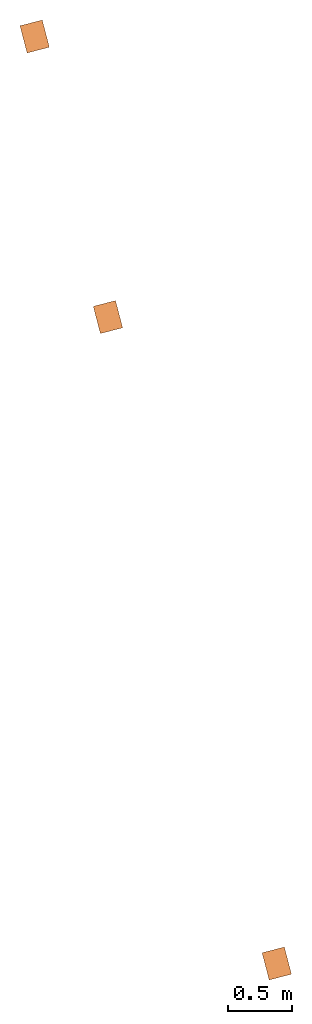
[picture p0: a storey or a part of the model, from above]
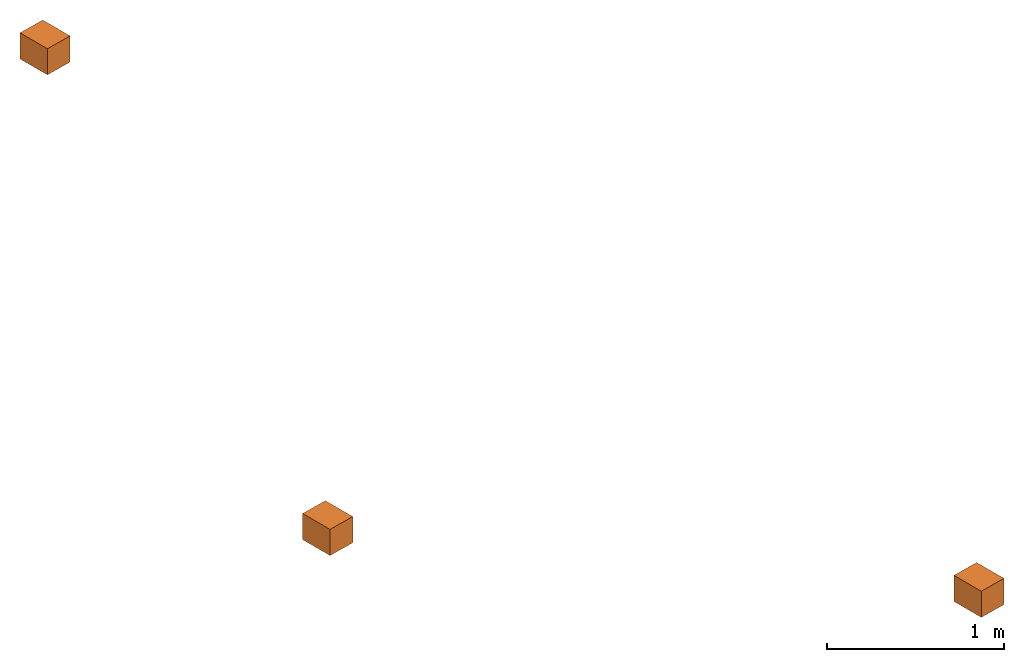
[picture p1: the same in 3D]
Properties of the parts of a building model (IFC2X3), part 1 of 2

# File
Description: ViewDefinition [CoordinationView_V2.0]
Time: 2019-01-15T11:54:13
Written by: The EXPRESS Data Manager Version 5.02.0100.07 : 28 Aug 2013
Made in: 20170223_1515(x64) - Exporter 18.0.0.420 - Alternate UI 18.0.0.420
Comment: STEP Physical File produced by: The EXPRESS Data Manager Version 5.02.0100.07 : 28 Aug 2013 * Module: EDMstepFileFactory/EDMstandAlone * Creation date: Tue Jan 15 11:54:13 2019 * Host: p130-T5-12 * Database: C:\Users\bac\AppData\Local\Temp\{CE2FFFC3-3B57-4D53-86EA-6668387194BC}\ifc * Database version: 5507 * Database creation date: Tue Jan 15 11:53:54 2019 * Schema: IFC2X3 * Model: DataRepository.ifc * Model creation date: Tue Jan 15 11:53:54 2019 * Header model: DataRepository.ifc_HeaderModel * Header model creation date: Tue Jan 15 11:53:54 2019 * EDMuser: sdai-user * EDMgroup: sdai-group * License ID and type: 5605 : Permanent license. Expiry date: * EDMstepFileFactory options: 020000

# IfcProject
LongName: LE HAVRE - LECESNE - 58 HN

# IfcSite, Default
RefLatitude: 49, 29, 35, 967407; RefLongitude: 0, 7, 10, 411264; RefElevation: 400 cm

# IfcBuilding, CAGE 03
LongName: CAGE 03
Pset_BuildingCommon - NumberOfStoreys: 22

# IfcBuildingStorey (22)
In: CAGE 03
Name | LongName | Elevation (cm)
±0.00 | ±0.00 | -400
+3.45 | +3.45 | -55
+3.50 | +3.50 | -50
+3.53 | +3.53 | -47
+3.58 | +3.58 | -42
+3.61 | +3.61 | -39
+3.66 | +3.66 | -34
+3.69 | +3.69 | -31
+3.74 | +3.74 | -26
+3.77 | +3.77 | -23
RDC | RDC | -1.08287e-13
Ac RDC | Ac RDC | 65
R+1 | R+1 | 340
Ac R+1 | Ac R+1 | 385
R+2 | R+2 | 610
Ac R+2 | Ac R+2 | 675
R+3 | R+3 | 880
Ac R+3 | Ac R+3 | 968
R+4 | R+4 | 1150
R+5 | R+5 | 1420
R+6 | R+6 | 1690
Acrotère | Acrotère | 1795

# IfcBeam: 100x20ht (4)
Type - ElementType: 100x20ht; PredefinedType: BEAM; Material: Béton, C25/30
Pset_BeamCommon - LoadBearing: yes; IsExternal: no; Slope: 0 deg; Reference: 100x20ht; Span: 366 cm
Name (BBGO-Poutre rect:100x20ht:...) | In
1579181 | R+5
1588789 | R+4
1595613 | R+3
1606648 | R+2

# IfcBeam: 16x20ht (2)
In: R+2
Type - ElementType: 16x20ht; PredefinedType: BEAM; Material: Béton, C25/30
Pset_BeamCommon - LoadBearing: yes; IsExternal: no; Slope: 0 deg; Reference: 16x20ht
Name (BBGO-Poutre rect:16x20ht:...) | Span (cm)
1604822 | 124
1604825 | 122

# IfcBeam: 18x20ht (14)
Type - ElementType: 18x20ht; PredefinedType: BEAM; Material: Béton, C25/30
Pset_BeamCommon - LoadBearing: yes; IsExternal: no; Slope: 0 deg; Reference: 18x20ht
Name (BBGO-Poutre rect:18x20ht:...) | In | Span (cm)
1467736 | R+5 | 140
1467887 | R+5 | 140
1471738 | R+4 | 122
1594888 | R+3 | 140
1594921 | R+3 | 151.5
1595572 | R+3 | 151.5
1602779 | R+2 | 194
1602781 | R+2 | 200
1604551 | R+2 | 201
1604553 | R+2 | 207
1604658 | R+2 | 194
1604660 | R+2 | 200
1604741 | R+2 | 201
1604743 | R+2 | 207

# IfcBeam: 20x20ht (20)
Type - ElementType: 20x20ht; PredefinedType: BEAM; Material: Béton, C25/30
Pset_BeamCommon - LoadBearing: yes; IsExternal: no; Slope: 0 deg; Reference: 20x20ht
Name (BBGO-Poutre rect:20x20ht:...) | In | Span (cm)
1464487 | R+5 | 155.146
1469260 | R+5 | 160.277
1470163 | R+4 | 155.146
1471747 | R+4 | 160.277
1523368 | R+6 | 164
1580110 | R+5 | 188.891
1588794 | R+4 | 188.891
1594171 | R+3 | 155.146
1595688 | R+3 | 92.2657
1603458 | R+2 | 183.175
1606651 | R+2 | 92.2657
1664121 | R+5 | 154
1664836 | R+4 | 164
1665448 | R+3 | 164
1666531 | R+2 | 164
1666589 | R+2 | 140
1666734 | R+2 | 122
1755034 | +3.66 | 147
1775143 | +3.74 | 147
1775324 | +3.58 | 125

# IfcBeam: 30x20ht (2)
Type - ElementType: 30x20ht; PredefinedType: BEAM; Material: Béton, C25/30
Pset_BeamCommon - LoadBearing: yes; IsExternal: no; Slope: 0 deg; Reference: 30x20ht; Span: 170.852 cm
Name (BBGO-Poutre rect:30x20ht:...) | In
1468716 | R+5
1588786 | R+4

# IfcBeam: 40x20ht, BBGO-Poutre rect:40x20ht:1666184
In: R+2
Type - ElementType: 40x20ht; PredefinedType: BEAM; Material: Béton, C25/30
Pset_BeamCommon - LoadBearing: yes; IsExternal: no; Slope: 0 deg; Reference: 40x20ht; Span: 251 cm

# IfcBeam: 40x23ht, BBGO-Poutre rect:40x23ht:3285993
In: R+1
Type - ElementType: 40x23ht; PredefinedType: BEAM; Material: Béton, C25/30
Pset_BeamCommon - LoadBearing: yes; IsExternal: no; Slope: 0 deg; Reference: 40x23ht; Span: 178 cm

# IfcBeam: 40x80ht, BBGO-Poutre rect:40x80ht:3182657
In: +3.58
Type - ElementType: 40x80ht; PredefinedType: BEAM; Material: Béton, C25/30
Pset_BeamCommon - LoadBearing: yes; IsExternal: no; Slope: 0 deg; Reference: 40x80ht; Span: 398 cm

# IfcBeam: 40x80ht (26)
Type - ElementType: 40x80ht; PredefinedType: BEAM; Material: Béton, C25/30, <Unnamed>
Pset_BeamCommon - LoadBearing: yes; IsExternal: no; Slope: 0 deg; Reference: 40x80ht
Name (BBGO-Poutre rect:40x80ht:...) | In | Span (cm) | Material
1390465 | R+1 | 468
1396344 | R+1 | 576 | Béton, C25/30
1403484 | R+1 | 399 | Béton, C25/30
1404484 | R+1 | 399.771 | Béton, C25/30
1404595 | R+1 | 178.243 | Béton, C25/30
1404652 | R+1 | 534.499 | Béton, C25/30
1683414 | +3.66 | 256.5 | Béton, C25/30
1686917 | +3.74 | 457 | Béton, C25/30
1687021 | +3.74 | 515 | Béton, C25/30
1687140 | +3.58 | 515 | Béton, C25/30
1687440 | +3.58 | 453.5 | Béton, C25/30
1687557 | +3.58 | 741.5 | Béton, C25/30
1687639 | +3.58 | 579 | Béton, C25/30
1687887 | +3.66 | 692.919 | Béton, C25/30
1690029 | +3.66 | 464 | Béton, C25/30
1690128 | +3.66 | 501 | Béton, C25/30
1692204 | +3.66 | 640.137 | Béton, C25/30
1702050 | +3.74 | 510 | Béton, C25/30
1702220 | +3.74 | 511 | Béton, C25/30
1702897 | +3.74 | 656 | Béton, C25/30
1703066 | +3.58 | 515 | Béton, C25/30
1703503 | +3.58 | 706 | Béton, C25/30
1704326 | +3.58 | 260 | Béton, C25/30
1704421 | +3.58 | 480 | Béton, C25/30
1707273 | +3.50 | 537 | Béton, C25/30
1708009 | +3.50 | 284.5 | Béton, C25/30

# IfcBeam: 50x20ht (2)
Type - ElementType: 50x20ht; PredefinedType: BEAM; Material: Béton, C25/30
Pset_BeamCommon - LoadBearing: yes; IsExternal: no; Slope: 0 deg; Reference: 50x20ht; Span: 263 cm
Name (BBGO-Poutre rect:50x20ht:...) | In
1467465 | R+5
1588782 | R+4

# IfcBeam: 50x70ht, BBGO-Poutre rect:50x70ht:1394691
In: R+1
Type - ElementType: 50x70ht; PredefinedType: BEAM; Material: Béton, C25/30
Pset_BeamCommon - LoadBearing: yes; IsExternal: no; Slope: 0 deg; Reference: 50x70ht; Span: 135.263 cm

# IfcBeam: 70x100ht, BBGO-Poutre rect:70x100ht:3188013
In: +3.50
Type - ElementType: 70x100ht; PredefinedType: BEAM; Material: Béton, C25/30
Pset_BeamCommon - LoadBearing: yes; IsExternal: no; Slope: 0 deg; Reference: 70x100ht; Span: 320.487 cm

# IfcBeam: 70x20ht (2)
Type - ElementType: 70x20ht; PredefinedType: BEAM; Material: Béton, C25/30
Pset_BeamCommon - LoadBearing: yes; IsExternal: no; Slope: 0 deg; Reference: 70x20ht; Span: 291.5 cm
Name (BBGO-Poutre rect:70x20ht:...) | In
1467127 | R+5
1588775 | R+4

# IfcBeam: 70x80ht, BBGO-Poutre rect:70x80ht:1686509
In: +3.66
Type - ElementType: 70x80ht; PredefinedType: BEAM; Material: Béton, C25/30
Pset_BeamCommon - LoadBearing: yes; IsExternal: no; Slope: 0 deg; Reference: 70x80ht; Span: 754 cm

# IfcBeam: 80x100ht, BBGO-Poutre rect:80x100ht:1634485
In: R+1
Type - ElementType: 80x100ht; PredefinedType: BEAM; Material: Béton, C25/30
Pset_BeamCommon - LoadBearing: yes; IsExternal: no; Slope: 0 deg; Reference: 80x100ht; Span: 926.545 cm

# IfcBeam: BBGO-Poutre rect:100x100ht, BBGO-Poutre rect:100x100ht:1693027
In: +3.66
Type - PredefinedType: BEAM
Material: Béton, C25/30
Pset_BeamCommon - LoadBearing: yes; IsExternal: no; Slope: 0 deg; Reference: 100x100ht; Span: 349.714 cm

# IfcBeam: BBGO-Poutre rect:16x50ht (2)
In: R+3
Type - PredefinedType: BEAM
Material: Béton, C25/30
Pset_BeamCommon - LoadBearing: yes; IsExternal: no; Slope: 0 deg; Reference: 16x50ht; Span: 124 cm
Name (BBGO-Poutre rect:16x50ht:...)
1594637
1595212

# IfcBeam: BBGO-Poutre rect:18x100ht, BBGO-Poutre rect:18x100ht:1404859
In: R+1
Type - PredefinedType: BEAM
Material: Béton, C25/30
Pset_BeamCommon - LoadBearing: yes; IsExternal: no; Slope: 0 deg; Reference: 18x100ht; Span: 574.707 cm

# IfcBeam: BBGO-Poutre rect:18x113ht (3)
Type - PredefinedType: BEAM
Material: Béton, C25/30
Pset_BeamCommon - LoadBearing: yes; IsExternal: no; Slope: 0 deg; Reference: 18x113ht; Span: 178 cm
Name (BBGO-Poutre rect:18x113ht:...) | In
1701175 | +3.66
1701721 | +3.74
1703309 | +3.58

# IfcBeam: BBGO-Poutre rect:18x115ht (9)
Type - PredefinedType: BEAM
Material: Béton, C25/30
Pset_BeamCommon - LoadBearing: yes; IsExternal: no; Slope: 0 deg; Reference: 18x115ht
Name (BBGO-Poutre rect:18x115ht:...) | In | Span (cm)
1701300 | +3.66 | 187
1701547 | +3.66 | 329
1701560 | +3.66 | 207
1701719 | +3.74 | 187
1701723 | +3.74 | 340
1701725 | +3.74 | 207
1703307 | +3.58 | 187
1703311 | +3.58 | 329
1703313 | +3.58 | 320

# IfcBeam: BBGO-Poutre rect:18x149ht (7)
Type - PredefinedType: BEAM
Material: Béton, C25/30
Pset_BeamCommon - LoadBearing: yes; IsExternal: no; Slope: 0 deg; Reference: 18x149ht
Name (BBGO-Poutre rect:18x149ht:...) | In | Span (cm)
1460876 | Acrotère | 566.165
1462445 | R+5 | 617.413
1462552 | R+5 | 480
1462619 | R+5 | 482
1462693 | R+5 | 480
1471988 | R+5 | 553.046
1472036 | R+5 | 222.13

# IfcBeam: BBGO-Poutre rect:18x35ht (4)
Type - PredefinedType: BEAM
Material: Béton, C25/30
Pset_BeamCommon - LoadBearing: yes; IsExternal: no; Slope: 0 deg; Reference: 18x35ht
Name (BBGO-Poutre rect:18x35ht:...) | In | Span (cm)
1469084 | R+5 | 233
1469165 | R+5 | 378
1471741 | R+4 | 233
1471744 | R+4 | 378

# IfcBeam: BBGO-Poutre rect:18x40ht (6)
Type - PredefinedType: BEAM
Material: Béton, C25/30
Pset_BeamCommon - LoadBearing: yes; IsExternal: no; Slope: 0 deg; Reference: 18x40ht
Name (BBGO-Poutre rect:18x40ht:...) | In | Span (cm)
1460390 | R+6 | 430
1461010 | R+6 | 477.369
1594353 | R+3 | 218
1594355 | R+3 | 224
1595137 | R+3 | 218
1595139 | R+3 | 224

# IfcBeam: BBGO-Poutre rect:18x44ht (4)
In: R+6
Type - PredefinedType: BEAM
Material: Béton, C25/30
Pset_BeamCommon - LoadBearing: yes; IsExternal: no; Slope: 0 deg; Reference: 18x44ht
Name (BBGO-Poutre rect:18x44ht:...) | Span (cm)
1456528 | 221.652
1456573 | 318.081
1460520 | 189
1460558 | 410

# IfcBeam: BBGO-Poutre rect:18x45ht (4)
In: R+1
Type - PredefinedType: BEAM
Material: Béton, C25/30
Pset_BeamCommon - LoadBearing: yes; IsExternal: no; Slope: 0 deg; Reference: 18x45ht
Name (BBGO-Poutre rect:18x45ht:...) | Span (cm)
1393045 | 282
1407809 | 284
1407833 | 282
1428806 | 158.699

# IfcBeam: BBGO-Poutre rect:18x50ht (4)
In: R+3
Type - PredefinedType: BEAM
Material: Béton, C25/30
Pset_BeamCommon - LoadBearing: yes; IsExternal: no; Slope: 0 deg; Reference: 18x50ht
Name (BBGO-Poutre rect:18x50ht:...) | Span (cm)
1594244 | 218
1594278 | 224
1595274 | 218
1595276 | 224

# IfcBeam: BBGO-Poutre rect:18x60ht (6)
Type - PredefinedType: BEAM
Material: Béton, C25/30
Pset_BeamCommon - LoadBearing: yes; IsExternal: no; Slope: 0 deg; Reference: 18x60ht
Name (BBGO-Poutre rect:18x60ht:...) | In | Span (cm)
1698657 | +3.74 | 267.586
1699916 | +3.74 | 514
1700543 | +3.74 | 524
1700562 | +3.74 | 274
1700807 | +3.74 | 514
1704848 | +3.58 | 538

# IfcBeam: BBGO-Poutre rect:18x62ht (5)
In: R+1
Type - PredefinedType: BEAM
Material: Béton, C25/30
Pset_BeamCommon - LoadBearing: yes; IsExternal: no; Reference: 18x62ht; Slope: 0 deg
Name (BBGO-Poutre rect:18x62ht:...) | Span (cm)
1387844 | 489
1388128 | 303
1388225 | 209.113
1408479 | 86.4551
1408550 | 272.054

# IfcBeam: BBGO-Poutre rect:18x70ht, BBGO-Poutre rect:18x70ht:1689230
In: +3.66
Type - PredefinedType: BEAM
Material: Béton, C25/30
Pset_BeamCommon - LoadBearing: yes; IsExternal: no; Slope: 0 deg; Reference: 18x70ht; Span: 459 cm

# IfcBeam: BBGO-Poutre rect:18x75ht, BBGO-Poutre rect:18x75ht:1685928
In: +3.74
Type - PredefinedType: BEAM
Material: Béton, C25/30
Pset_BeamCommon - LoadBearing: yes; IsExternal: no; Slope: 0 deg; Reference: 18x75ht; Span: 484 cm

# IfcBeam: BBGO-Poutre rect:18x80ht (9)
Type - PredefinedType: BEAM
Material: Béton, C25/30
Pset_BeamCommon - LoadBearing: yes; IsExternal: no; Slope: 0 deg; Reference: 18x80ht
Name (BBGO-Poutre rect:18x80ht:...) | In | Span (cm)
1678249 | +3.66 | 586
1684312 | +3.66 | 469
1685654 | +3.74 | 491
1701363 | +3.66 | 156
1701836 | +3.74 | 156
1703319 | +3.58 | 156
1705288 | +3.58 | 252.441
1717493 | +3.58 | 69
1758508 | +3.74 | 15

# IfcBeam: BBGO-Poutre rect:18x89ht (18)
Type - PredefinedType: BEAM
Material: Béton, C25/30
Pset_BeamCommon - LoadBearing: yes; IsExternal: no; Slope: 0 deg; Reference: 18x89ht
Name (BBGO-Poutre rect:18x89ht:...) | In | Span (cm)
1470154 | R+4 | 480
1470156 | R+4 | 482
1470158 | R+4 | 480
1471070 | R+3 | 480
1471072 | R+3 | 482
1471074 | R+3 | 480
1471102 | R+2 | 480
1471104 | R+2 | 482
1471106 | R+2 | 480
1471449 | R+4 | 617.413
1471840 | R+4 | 553.046
1471866 | R+4 | 222.13
1478545 | R+3 | 617.413
1478831 | R+3 | 553.046
1478833 | R+3 | 222.13
1479287 | R+2 | 617.413
1479291 | R+2 | 553.046
1479293 | R+2 | 222.13

# IfcBeam: BBGO-Poutre rect:25x45ht (2)
In: R+1
Type - PredefinedType: BEAM
Material: Béton, C25/30
Pset_BeamCommon - LoadBearing: yes; IsExternal: no; Slope: 0 deg; Reference: 25x45ht
Name (BBGO-Poutre rect:25x45ht:...) | Span (cm)
1394172 | 183
1406665 | 176

# IfcBeam: BBGO-Poutre rect:25x60ht (2)
In: +3.74
Type - PredefinedType: BEAM
Material: Béton, C25/30
Pset_BeamCommon - LoadBearing: yes; IsExternal: no; Slope: 0 deg; Reference: 25x60ht
Name (BBGO-Poutre rect:25x60ht:...) | Span (cm)
1691024 | 495
1691301 | 647

# IfcBeam: BBGO-Poutre rect:25x75ht, BBGO-Poutre rect:25x75ht:1702517
In: +3.74
Type - PredefinedType: BEAM
Material: Béton, C25/30
Pset_BeamCommon - LoadBearing: yes; IsExternal: no; Slope: 0 deg; Reference: 25x75ht; Span: 493 cm

# IfcBeam: BBGO-Poutre rect:25x80ht (5)
Type - PredefinedType: BEAM
Material: Béton, C25/30
Pset_BeamCommon - LoadBearing: yes; IsExternal: no; Slope: 0 deg; Reference: 25x80ht
Name (BBGO-Poutre rect:25x80ht:...) | In | Span (cm)
1699639 | +3.66 | 695
1702635 | +3.74 | 334
1707469 | +3.50 | 314.814
1707831 | +3.50 | 528.138
1708224 | +3.50 | 291.294

# IfcBeam: BBGO-Poutre rect:30x45ht (2)
In: R+1
Type - PredefinedType: BEAM
Material: Béton, C25/30
Pset_BeamCommon - LoadBearing: yes; IsExternal: no; Slope: 0 deg; Reference: 30x45ht
Name (BBGO-Poutre rect:30x45ht:...) | Span (cm)
1401985 | 260.5
1402226 | 237

# IfcBeam: BBGO-Poutre rect:30x50ht, BBGO-Poutre rect:30x50ht:2342210
In: R+1
Type - PredefinedType: BEAM
Material: Béton, C25/30
Pset_BeamCommon - LoadBearing: yes; IsExternal: no; Slope: 0 deg; Reference: 30x50ht; Span: 419.826 cm

# IfcBeam: BBGO-Poutre rect:30x60ht (4)
In: +3.50
Type - PredefinedType: BEAM
Material: Béton, C25/30
Pset_BeamCommon - LoadBearing: yes; IsExternal: no; Slope: 0 deg; Reference: 30x60ht; Span: 350 cm
Name (BBGO-Poutre rect:30x60ht:...)
3117109
3117535
3117598
3117718

# IfcBeam: BBGO-Poutre rect:30x80ht (10)
Type - PredefinedType: BEAM
Material: Béton, C25/30
Pset_BeamCommon - LoadBearing: yes; IsExternal: no; Slope: 0 deg; Reference: 30x80ht
Name (BBGO-Poutre rect:30x80ht:...) | In | Span (cm)
1689533 | +3.66 | 510
1691867 | +3.77 | 371.045
1692765 | +3.66 | 624.328
1693319 | +3.66 | 186.5
1699210 | +3.74 | 343
1707919 | +3.50 | 348.438
2337563 | +3.74 | 225
2337755 | +3.74 | 225
2340572 | +3.74 | 143
2340669 | +3.74 | 143

# IfcBeam: BBGO-Poutre rect:30x86ht, BBGO-Poutre rect:30x86ht:1692640
In: +3.77
Type - PredefinedType: BEAM
Material: Béton, C25/30
Pset_BeamCommon - LoadBearing: yes; IsExternal: no; Slope: 0 deg; Reference: 30x86ht; Span: 289 cm

# IfcBeam: BBGO-Poutre rect:35x100ht (4)
In: R+1
Type - PredefinedType: BEAM
Material: Béton, C25/30
Pset_BeamCommon - LoadBearing: yes; IsExternal: no; Slope: 0 deg; Reference: 35x100ht
Name (BBGO-Poutre rect:35x100ht:...) | Span (cm)
1401092 | 227
1401320 | 233
1401492 | 227
1401494 | 233

# IfcBeam: BBGO-Poutre rect:35x44ht, BBGO-Poutre rect:35x44ht:1456888
In: R+6
Type - PredefinedType: BEAM
Material: Béton, C25/30
Pset_BeamCommon - LoadBearing: yes; IsExternal: no; Slope: 0 deg; Reference: 35x44ht; Span: 798 cm

# IfcBeam: BBGO-Poutre rect:35x75ht (2)
In: R+1
Type - PredefinedType: BEAM
Material: Béton, C25/30
Pset_BeamCommon - LoadBearing: yes; IsExternal: no; Slope: 0 deg; Reference: 35x75ht; Span: 156 cm
Name (BBGO-Poutre rect:35x75ht:...)
1645117
1645243

# IfcBeam: BBGO-Poutre rect:35x80ht (2)
In: +3.58
Type - PredefinedType: BEAM
Material: Béton, C25/30
Pset_BeamCommon - LoadBearing: yes; IsExternal: no; Slope: 0 deg; Reference: 35x80ht
Name (BBGO-Poutre rect:35x80ht:...) | Span (cm)
1703919 | 660
1704288 | 252

# IfcBeam: BBGO-Poutre rect:36x101ht (2)
In: +3.66
Type - PredefinedType: BEAM
Material: Béton, C25/30
Pset_BeamCommon - LoadBearing: yes; IsExternal: no; Slope: 0 deg; Reference: 36x101ht
Name (BBGO-Poutre rect:36x101ht:...) | Span (cm)
1706288 | 539.344
1706487 | 410.66

# IfcBeam: BBGO-Poutre rect:40x100ht (15)
In: R+1
Type - PredefinedType: BEAM
Material: Béton, C25/30
Pset_BeamCommon - LoadBearing: yes; IsExternal: no; Slope: 0 deg; Reference: 40x100ht
Name (BBGO-Poutre rect:40x100ht:...) | Span (cm)
1392234 | 480.5
1392454 | 397.391
1392599 | 516.5
1393220 | 752.5
1394944 | 437.5
1395088 | 455
1395167 | 237
1395228 | 237
1395267 | 227
1395270 | 227
1396259 | 152
1400642 | 281.5
1400772 | 330.5
1400857 | 433.499
1402557 | 106.501

# IfcBeam: BBGO-Poutre rect:40x16ht (2)
In: R+3
Type - PredefinedType: BEAM
Material: Béton, C25/30
Pset_BeamCommon - LoadBearing: yes; IsExternal: no; Slope: 0 deg; Reference: 40x16ht
Name (BBGO-Poutre rect:40x16ht:...) | Span (cm)
2397350 | 34
2398709 | 39

# IfcBeam: BBGO-Poutre rect:40x60ht (4)
Type - PredefinedType: BEAM
Material: Béton, C25/30
Pset_BeamCommon - LoadBearing: yes; IsExternal: no; Slope: 0 deg; Reference: 40x60ht
Name (BBGO-Poutre rect:40x60ht:...) | In | Span (cm)
1392805 | R+1 | 360.5
1401913 | R+1 | 389
1698551 | +3.74 | 569
3285272 | R+1 | 199.436

# IfcBeam: BBGO-Poutre rect:40x70ht (3)
In: R+1
Type - PredefinedType: BEAM
Material: Béton, C25/30
Pset_BeamCommon - LoadBearing: yes; IsExternal: no; Slope: 0 deg; Reference: 40x70ht
Name (BBGO-Poutre rect:40x70ht:...) | Span (cm)
1396079 | 368
1401577 | 389
1406589 | 256.5

# IfcBeam: BBGO-Poutre rect:40x75ht (3)
In: R+1
Type - PredefinedType: BEAM
Material: Béton, C25/30
Pset_BeamCommon - LoadBearing: yes; IsExternal: no; Slope: 0 deg; Reference: 40x75ht
Name (BBGO-Poutre rect:40x75ht:...) | Span (cm)
1633729 | 197
1644679 | 188.5
1644749 | 188.5

# IfcBeam: BBGO-Poutre rect:40x90ht (7)
In: R+1
Type - PredefinedType: BEAM
Material: Béton, C25/30
Pset_BeamCommon - LoadBearing: yes; IsExternal: no; Slope: 0 deg; Reference: 40x90ht
Name (BBGO-Poutre rect:40x90ht:...) | Span (cm)
1397843 | 544
1398095 | 274
1400056 | 544
1400127 | 274
1403041 | 695
1403301 | 580
1403924 | 569

# IfcBeam: BBGO-Poutre rect:40x91ht (2)
In: +3.77
Type - PredefinedType: BEAM
Material: Béton, C25/30
Pset_BeamCommon - LoadBearing: yes; IsExternal: no; Slope: 0 deg; Reference: 40x91ht
Name (BBGO-Poutre rect:40x91ht:...) | Span (cm)
1691365 | 106
1692473 | 244.674

# IfcBeam: BBGO-Poutre rect:45x101ht (2)
In: +3.66
Type - PredefinedType: BEAM
Material: Béton, C25/30
Pset_BeamCommon - LoadBearing: yes; IsExternal: no; Slope: 0 deg; Reference: 45x101ht
Name (BBGO-Poutre rect:45x101ht:...) | Span (cm)
1705961 | 470.752
1706576 | 483.612

# IfcBeam: BBGO-Poutre rect:45x80ht, BBGO-Poutre rect:45x80ht:1704699
In: +3.58
Type - PredefinedType: BEAM
Material: Béton, C25/30
Pset_BeamCommon - LoadBearing: yes; IsExternal: no; Slope: 0 deg; Reference: 45x80ht; Span: 256.5 cm

# IfcBeam: BBGO-Poutre rect:50x100ht (7)
In: R+1
Type - PredefinedType: BEAM
Material: Béton, C25/30
Pset_BeamCommon - LoadBearing: yes; IsExternal: no; Slope: 0 deg; Reference: 50x100ht
Name (BBGO-Poutre rect:50x100ht:...) | Span (cm)
1393466 | 695
1398620 | 489
1398963 | 590
1399015 | 501
1402654 | 747
1402804 | 540
1402851 | 609

# IfcBeam: BBGO-Poutre rect:50x110ht, BBGO-Poutre rect:50x110ht:1700393
In: +3.74
Type - PredefinedType: BEAM
Material: Béton, C25/30
Pset_BeamCommon - LoadBearing: yes; IsExternal: no; Slope: 0 deg; Reference: 50x110ht; Span: 532 cm

# IfcBeam: BBGO-Poutre rect:50x70ht (2)
In: R+1
Type - PredefinedType: BEAM
Material: Béton, C25/30
Pset_BeamCommon - LoadBearing: yes; IsExternal: no; Slope: 0 deg; Reference: 50x70ht
Name (BBGO-Poutre rect:50x70ht:...) | Span (cm)
1394042 | 575
1407037 | 403

# IfcBeam: BBGO-Poutre rect:50x80ht (3)
Type - PredefinedType: BEAM
Material: Béton, C25/30
Pset_BeamCommon - LoadBearing: yes; IsExternal: no; Slope: 0 deg; Reference: 50x80ht
Name (BBGO-Poutre rect:50x80ht:...) | In | Span (cm)
1390898 | R+1 | 459
1407191 | R+1 | 528
1707155 | +3.50 | 488.376

# IfcBeam: BBGO-Poutre rect:50x90ht, BBGO-Poutre rect:50x90ht:1390707
In: R+1
Type - PredefinedType: BEAM
Material: Béton, C25/30
Pset_BeamCommon - LoadBearing: yes; IsExternal: no; Slope: 0 deg; Reference: 50x90ht; Span: 468 cm

# IfcBeam: BBGO-Poutre rect:51x45ht, BBGO-Poutre rect:51x45ht:1428907
In: R+1
Type - PredefinedType: BEAM
Material: Béton, C25/30
Pset_BeamCommon - LoadBearing: yes; IsExternal: no; Slope: 0 deg; Reference: 51x45ht; Span: 296.018 cm

# IfcBeam: BBGO-Poutre rect:55x107ht (2)
In: +3.66
Type - PredefinedType: BEAM
Material: Béton, C25/30
Pset_BeamCommon - LoadBearing: yes; IsExternal: no; Slope: 0 deg; Reference: 55x107ht
Name (BBGO-Poutre rect:55x107ht:...) | Span (cm)
1688491 | 164.022
1689137 | 498

# IfcBeam: BBGO-Poutre rect:55x80ht, BBGO-Poutre rect:55x80ht:1688154
In: +3.66
Type - PredefinedType: BEAM
Material: Béton, C25/30
Pset_BeamCommon - LoadBearing: yes; IsExternal: no; Slope: 0 deg; Reference: 55x80ht; Span: 450 cm

# IfcBeam: BBGO-Poutre rect:60x100ht (3)
In: R+1
Type - PredefinedType: BEAM
Material: Béton, C25/30
Pset_BeamCommon - LoadBearing: yes; IsExternal: no; Slope: 0 deg; Reference: 60x100ht
Name (BBGO-Poutre rect:60x100ht:...) | Span (cm)
1397119 | 862
1398215 | 791
1400321 | 867

# IfcBeam: BBGO-Poutre rect:60x80ht (6)
Type - PredefinedType: BEAM
Material: Béton, C25/30
Pset_BeamCommon - LoadBearing: yes; IsExternal: no; Slope: 0 deg; Reference: 60x80ht
Name (BBGO-Poutre rect:60x80ht:...) | In | Span (cm)
1687762 | +3.66 | 135.453
1688713 | +3.66 | 596.5
1697774 | +3.74 | 102.188
1698284 | +3.74 | 568.85
1700316 | +3.74 | 519
2341871 | +3.66 | 322

# IfcBeam: BBGO-Poutre rect:60x90ht (3)
In: R+1
Type - PredefinedType: BEAM
Material: Béton, C25/30
Pset_BeamCommon - LoadBearing: yes; IsExternal: no; Slope: 0 deg; Reference: 60x90ht
Name (BBGO-Poutre rect:60x90ht:...) | Span (cm)
1391032 | 559
1391274 | 575
1392754 | 566.5

# IfcBeam: BBGO-Poutre rect:65x100ht, BBGO-Poutre rect:65x100ht:1692812
In: +3.66
Type - PredefinedType: BEAM
Material: Béton, C25/30
Pset_BeamCommon - LoadBearing: yes; IsExternal: no; Slope: 0 deg; Reference: 65x100ht; Span: 847.105 cm

# IfcBeam: BBGO-Poutre rect:65x45ht (3)
In: R+1
Type - PredefinedType: BEAM
Material: Béton, C25/30
Pset_BeamCommon - LoadBearing: yes; IsExternal: no; Slope: 0 deg; Reference: 65x45ht
Name (BBGO-Poutre rect:65x45ht:...) | Span (cm)
1396215 | 495
1396510 | 495
1401807 | 497.5

# IfcBeam: BBGO-Poutre rect:70x80ht (3)
In: +3.74
Type - PredefinedType: BEAM
Material: Béton, C25/30
Pset_BeamCommon - LoadBearing: yes; IsExternal: no; Slope: 0 deg; Reference: 70x80ht
Name (BBGO-Poutre rect:70x80ht:...) | Span (cm)
1684769 | 487
1685497 | 804
1716617 | 661

# IfcBeam: BBGO-Poutre rect:70x90ht (2)
In: R+1
Type - PredefinedType: BEAM
Material: Béton, C25/30
Pset_BeamCommon - LoadBearing: yes; IsExternal: no; Slope: 0 deg; Reference: 70x90ht
Name (BBGO-Poutre rect:70x90ht:...) | Span (cm)
1398422 | 575
1399689 | 580

# IfcBeam: BBGO-Poutre rect:80x100ht (5)
Type - PredefinedType: BEAM
Material: Béton, C25/30
Pset_BeamCommon - LoadBearing: yes; IsExternal: no; Slope: 0 deg; Reference: 80x100ht
Name (BBGO-Poutre rect:80x100ht:...) | In | Span (cm)
1402473 | R+1 | 867
1705394 | +3.50 | 91.0043
1705895 | +3.50 | 521.4
3184185 | +3.58 | 170
3186767 | +3.58 | 510.114

# IfcBeam: BBGO-Poutre rect:80x45ht, BBGO-Poutre rect:80x45ht:1388635
In: R+1
Type - PredefinedType: BEAM
Material: Béton, C25/30
Pset_BeamCommon - LoadBearing: yes; IsExternal: no; Slope: 0 deg; Reference: 80x45ht; Span: 256.5 cm

# IfcBeam: BBGO-Poutre rect:80x80ht (4)
Type - PredefinedType: BEAM
Material: Béton, C25/30
Pset_BeamCommon - LoadBearing: yes; IsExternal: no; Slope: 0 deg; Reference: 80x80ht
Name (BBGO-Poutre rect:80x80ht:...) | In | Span (cm)
1690715 | +3.66 | 255
1703595 | +3.58 | 498
2341290 | +3.66 | 152
2405490 | +3.77 | 407.373

# IfcBeam: BBGO-Poutre rect:90x70ht (2)
In: +3.74
Type - PredefinedType: BEAM
Material: Béton, C25/30
Pset_BeamCommon - LoadBearing: yes; IsExternal: no; Slope: 0 deg; Reference: 90x70ht
Name (BBGO-Poutre rect:90x70ht:...) | Span (cm)
1693658 | 902.783
1693866 | 42.2729

# IfcBeam: BBGO-Poutre rect:90x90ht, BBGO-Poutre rect:90x90ht:1399750
In: R+1
Type - PredefinedType: BEAM
Material: Béton, C25/30
Pset_BeamCommon - LoadBearing: yes; IsExternal: no; Slope: 0 deg; Reference: 90x90ht; Span: 850 cm

# IfcBeam: Cornière à ailes inégales:L80x60x7 (4)
In: +3.66
Type - PredefinedType: BEAM
Material: Acier structurel - S235
Pset_BeamCommon - LoadBearing: yes; IsExternal: no; Slope: 0 deg; Reference: L80x60x7
Name (Cornière à ailes inégales:L80x60x7:...) | Span (cm)
1879896 | 97.5
1881167 | 97.5
1881275 | 140
1881454 | 140

# IfcBeam: Cornière à ailes égales:L30x4 (3)
In: +3.66
Type - PredefinedType: BEAM
Material: Acier structurel - S235
Pset_BeamCommon - LoadBearing: yes; IsExternal: no; Slope: 0 deg; Reference: L30x4
Name (Cornière à ailes égales:L30x4:...) | Span (cm)
1878539 | 106
1878629 | 24.5
1879489 | 24.5

# IfcBuildingElementProxy: CFO100 P80 (45)
Type - Material: Circuit ECS Retour
Pset_BuildingElementProxyCommon - Reference: CFO100 P80
Name | In
Galette - Résa - PVC1:CFO100 P80:3861348 | R+2
Galette - Résa - PVC1:CFO100 P80:3861380 | R+2
Galette - Résa - PVC1:CFO100 P80:3861387 | R+2
Galette - Résa - PVC1:CFO100 P80:3861394 | R+2
Galette - Résa - PVC1:CFO100 P80:3861396 | R+2
Galette - Résa - PVC1:CFO100 P80:3861402 | R+2
Galette - Résa - PVC1:CFO100 P80:3861410 | R+2
Galette - Résa - PVC1:CFO100 P80:3861412 | R+2
Galette - Résa - PVC1:CFO100 P80:3861423 | R+2
Galette - Résa - PVC1:CFO100 P80:3861425 | R+2
Galette - Résa - PVC1:CFO100 P80:3861432 | R+2
Galette - Résa - PVC1:CFO100 P80:3861436 | R+2
Galette - Résa - PVC2:CFO100 P80:3880356 | R+3
Galette - Résa - PVC2:CFO100 P80:3880362 | R+3
Galette - Résa - PVC2:CFO100 P80:3880373 | R+3
Galette - Résa - PVC2:CFO100 P80:3880377 | R+3
Galette - Résa - PVC2:CFO100 P80:3880392 | R+3
Galette - Résa - PVC2:CFO100 P80:3880402 | R+3
Galette - Résa - PVC2:CFO100 P80:3880404 | R+3
Galette - Résa - PVC2:CFO100 P80:3880414 | R+3
Galette - Résa - PVC2:CFO100 P80:3880428 | R+3
Galette - Résa - PVC2:CFO100 P80:3880435 | R+3
Galette - Résa - PVC2:CFO100 P80:3880441 | R+3
Galette - Résa - PVC2:CFO100 P80:3880449 | R+3
Galette - Résa - PVC3:CFO100 P80:3882960 | R+4
Galette - Résa - PVC3:CFO100 P80:3882966 | R+4
Galette - Résa - PVC3:CFO100 P80:3882979 | R+4
Galette - Résa - PVC3:CFO100 P80:3882987 | R+4
Galette - Résa - PVC3:CFO100 P80:3882996 | R+4
Galette - Résa - PVC3:CFO100 P80:3882998 | R+4
Galette - Résa - PVC3:CFO100 P80:3883009 | R+4
Galette - Résa - PVC3:CFO100 P80:3883022 | R+4
Galette - Résa - PVC3:CFO100 P80:3883029 | R+4
Galette - Résa - PVC3:CFO100 P80:3883035 | R+4
Galette - Résa - PVC3:CFO100 P80:3883043 | R+4
Galette - Résa - PVC4:CFO100 P80:3885499 | R+5
Galette - Résa - PVC4:CFO100 P80:3885505 | R+5
Galette - Résa - PVC4:CFO100 P80:3885516 | R+5
Galette - Résa - PVC4:CFO100 P80:3885519 | R+5
Galette - Résa - PVC4:CFO100 P80:3885528 | R+5
Galette - Résa - PVC4:CFO100 P80:3885530 | R+5
Galette - Résa - PVC4:CFO100 P80:3885541 | R+5
Galette - Résa - PVC4:CFO100 P80:3885552 | R+5
Galette - Résa - PVC4:CFO100 P80:3885559 | R+5
Galette - Résa - PVC4:CFO100 P80:3885567 | R+5

# IfcBuildingElementProxy: CFO100 P90 (45)
Type - Material: Circuit ECS Aller
Pset_BuildingElementProxyCommon - Reference: CFO100 P90
Name | In
Galette - Résa - PVC1:CFO100 P90:3861347 | R+2
Galette - Résa - PVC1:CFO100 P90:3861379 | R+2
Galette - Résa - PVC1:CFO100 P90:3861386 | R+2
Galette - Résa - PVC1:CFO100 P90:3861393 | R+2
Galette - Résa - PVC1:CFO100 P90:3861395 | R+2
Galette - Résa - PVC1:CFO100 P90:3861401 | R+2
Galette - Résa - PVC1:CFO100 P90:3861409 | R+2
Galette - Résa - PVC1:CFO100 P90:3861411 | R+2
Galette - Résa - PVC1:CFO100 P90:3861422 | R+2
Galette - Résa - PVC1:CFO100 P90:3861424 | R+2
Galette - Résa - PVC1:CFO100 P90:3861433 | R+2
Galette - Résa - PVC1:CFO100 P90:3861435 | R+2
Galette - Résa - PVC2:CFO100 P90:3880357 | R+3
Galette - Résa - PVC2:CFO100 P90:3880361 | R+3
Galette - Résa - PVC2:CFO100 P90:3880372 | R+3
Galette - Résa - PVC2:CFO100 P90:3880376 | R+3
Galette - Résa - PVC2:CFO100 P90:3880391 | R+3
Galette - Résa - PVC2:CFO100 P90:3880401 | R+3
Galette - Résa - PVC2:CFO100 P90:3880403 | R+3
Galette - Résa - PVC2:CFO100 P90:3880413 | R+3
Galette - Résa - PVC2:CFO100 P90:3880427 | R+3
Galette - Résa - PVC2:CFO100 P90:3880436 | R+3
Galette - Résa - PVC2:CFO100 P90:3880440 | R+3
Galette - Résa - PVC2:CFO100 P90:3880448 | R+3
Galette - Résa - PVC3:CFO100 P90:3882961 | R+4
Galette - Résa - PVC3:CFO100 P90:3882965 | R+4
Galette - Résa - PVC3:CFO100 P90:3882978 | R+4
Galette - Résa - PVC3:CFO100 P90:3882986 | R+4
Galette - Résa - PVC3:CFO100 P90:3882995 | R+4
Galette - Résa - PVC3:CFO100 P90:3882997 | R+4
Galette - Résa - PVC3:CFO100 P90:3883008 | R+4
Galette - Résa - PVC3:CFO100 P90:3883021 | R+4
Galette - Résa - PVC3:CFO100 P90:3883030 | R+4
Galette - Résa - PVC3:CFO100 P90:3883036 | R+4
Galette - Résa - PVC3:CFO100 P90:3883042 | R+4
Galette - Résa - PVC4:CFO100 P90:3885500 | R+5
Galette - Résa - PVC4:CFO100 P90:3885504 | R+5
Galette - Résa - PVC4:CFO100 P90:3885515 | R+5
Galette - Résa - PVC4:CFO100 P90:3885518 | R+5
Galette - Résa - PVC4:CFO100 P90:3885527 | R+5
Galette - Résa - PVC4:CFO100 P90:3885529 | R+5
Galette - Résa - PVC4:CFO100 P90:3885540 | R+5
Galette - Résa - PVC4:CFO100 P90:3885551 | R+5
Galette - Résa - PVC4:CFO100 P90:3885560 | R+5
Galette - Résa - PVC4:CFO100 P90:3885566 | R+5

# IfcBuildingElementProxy: CFO125 P100, Galette - Résa - PVC:CFO125 P100:3841190
In: R+1
Type - Material: Circuit CHF Retour
Pset_BuildingElementProxyCommon - Reference: CFO125 P100

# IfcBuildingElementProxy: CFO125 P110 (149)
Type - Material: Conduit EU
Pset_BuildingElementProxyCommon - Reference: CFO125 P110
Name | In
Galette - Résa - PVC1:CFO125 P110:3861322 | R+2
Galette - Résa - PVC1:CFO125 P110:3861345 | R+2
Galette - Résa - PVC1:CFO125 P110:3861349 | R+2
Galette - Résa - PVC1:CFO125 P110:3861352 | R+2
Galette - Résa - PVC1:CFO125 P110:3861353 | R+2
Galette - Résa - PVC1:CFO125 P110:3861354 | R+2
Galette - Résa - PVC1:CFO125 P110:3861355 | R+2
Galette - Résa - PVC1:CFO125 P110:3861356 | R+2
Galette - Résa - PVC1:CFO125 P110:3861357 | R+2
Galette - Résa - PVC1:CFO125 P110:3861358 | R+2
Galette - Résa - PVC1:CFO125 P110:3861359 | R+2
Galette - Résa - PVC1:CFO125 P110:3861360 | R+2
Galette - Résa - PVC1:CFO125 P110:3861361 | R+2
Galette - Résa - PVC1:CFO125 P110:3861362 | R+2
Galette - Résa - PVC1:CFO125 P110:3861363 | R+2
Galette - Résa - PVC1:CFO125 P110:3861364 | R+2
Galette - Résa - PVC1:CFO125 P110:3861365 | R+2
Galette - Résa - PVC1:CFO125 P110:3861366 | R+2
Galette - Résa - PVC1:CFO125 P110:3861367 | R+2
Galette - Résa - PVC1:CFO125 P110:3861368 | R+2
Galette - Résa - PVC1:CFO125 P110:3861369 | R+2
Galette - Résa - PVC1:CFO125 P110:3861370 | R+2
Galette - Résa - PVC1:CFO125 P110:3861371 | R+2
Galette - Résa - PVC1:CFO125 P110:3861372 | R+2
Galette - Résa - PVC1:CFO125 P110:3861373 | R+2
Galette - Résa - PVC1:CFO125 P110:3861374 | R+2
Galette - Résa - PVC1:CFO125 P110:3861375 | R+2
Galette - Résa - PVC1:CFO125 P110:3861381 | R+2
Galette - Résa - PVC1:CFO125 P110:3861383 | R+2
Galette - Résa - PVC1:CFO125 P110:3861406 | R+2
Galette - Résa - PVC1:CFO125 P110:3861421 | R+2
Galette - Résa - PVC1:CFO125 P110:3861426 | R+2
Galette - Résa - PVC1:CFO125 P110:3861427 | R+2
Galette - Résa - PVC1:CFO125 P110:3861431 | R+2
Galette - Résa - PVC1:CFO125 P110:3861434 | R+2
Galette - Résa - PVC2:CFO125 P110:3880354 | R+3
Galette - Résa - PVC2:CFO125 P110:3880358 | R+3
Galette - Résa - PVC2:CFO125 P110:3880360 | R+3
Galette - Résa - PVC2:CFO125 P110:3880363 | R+3
Galette - Résa - PVC2:CFO125 P110:3880367 | R+3
Galette - Résa - PVC2:CFO125 P110:3880368 | R+3
Galette - Résa - PVC2:CFO125 P110:3880369 | R+3
Galette - Résa - PVC2:CFO125 P110:3880370 | R+3
Galette - Résa - PVC2:CFO125 P110:3880374 | R+3
Galette - Résa - PVC2:CFO125 P110:3880379 | R+3
Galette - Résa - PVC2:CFO125 P110:3880385 | R+3
Galette - Résa - PVC2:CFO125 P110:3880387 | R+3
Galette - Résa - PVC2:CFO125 P110:3880393 | R+3
Galette - Résa - PVC2:CFO125 P110:3880394 | R+3
Galette - Résa - PVC2:CFO125 P110:3880396 | R+3
Galette - Résa - PVC2:CFO125 P110:3880399 | R+3
Galette - Résa - PVC2:CFO125 P110:3880400 | R+3
Galette - Résa - PVC2:CFO125 P110:3880408 | R+3
Galette - Résa - PVC2:CFO125 P110:3880409 | R+3
Galette - Résa - PVC2:CFO125 P110:3880411 | R+3
Galette - Résa - PVC2:CFO125 P110:3880416 | R+3
Galette - Résa - PVC2:CFO125 P110:3880425 | R+3
Galette - Résa - PVC2:CFO125 P110:3880429 | R+3
Galette - Résa - PVC2:CFO125 P110:3880431 | R+3
Galette - Résa - PVC2:CFO125 P110:3880434 | R+3
Galette - Résa - PVC2:CFO125 P110:3880437 | R+3
Galette - Résa - PVC2:CFO125 P110:3880439 | R+3
Galette - Résa - PVC2:CFO125 P110:3880442 | R+3
Galette - Résa - PVC2:CFO125 P110:3880444 | R+3
Galette - Résa - PVC2:CFO125 P110:3880445 | R+3
Galette - Résa - PVC2:CFO125 P110:3880447 | R+3
Galette - Résa - PVC2:CFO125 P110:3880450 | R+3
Galette - Résa - PVC3:CFO125 P110:3882958 | R+4
Galette - Résa - PVC3:CFO125 P110:3882962 | R+4
Galette - Résa - PVC3:CFO125 P110:3882964 | R+4
Galette - Résa - PVC3:CFO125 P110:3882968 | R+4
Galette - Résa - PVC3:CFO125 P110:3882972 | R+4
Galette - Résa - PVC3:CFO125 P110:3882973 | R+4
Galette - Résa - PVC3:CFO125 P110:3882974 | R+4
Galette - Résa - PVC3:CFO125 P110:3882976 | R+4
Galette - Résa - PVC3:CFO125 P110:3882980 | R+4
Galette - Résa - PVC3:CFO125 P110:3882982 | R+4
Galette - Résa - PVC3:CFO125 P110:3882983 | R+4
Galette - Résa - PVC3:CFO125 P110:3882988 | R+4
Galette - Résa - PVC3:CFO125 P110:3882989 | R+4
Galette - Résa - PVC3:CFO125 P110:3882991 | R+4
Galette - Résa - PVC3:CFO125 P110:3882993 | R+4
Galette - Résa - PVC3:CFO125 P110:3882994 | R+4
Galette - Résa - PVC3:CFO125 P110:3883002 | R+4
Galette - Résa - PVC3:CFO125 P110:3883005 | R+4
Galette - Résa - PVC3:CFO125 P110:3883006 | R+4
Galette - Résa - PVC3:CFO125 P110:3883011 | R+4
Galette - Résa - PVC3:CFO125 P110:3883019 | R+4
Galette - Résa - PVC3:CFO125 P110:3883023 | R+4
Galette - Résa - PVC3:CFO125 P110:3883025 | R+4
Galette - Résa - PVC3:CFO125 P110:3883028 | R+4
Galette - Résa - PVC3:CFO125 P110:3883031 | R+4
Galette - Résa - PVC3:CFO125 P110:3883034 | R+4
Galette - Résa - PVC3:CFO125 P110:3883037 | R+4
Galette - Résa - PVC3:CFO125 P110:3883038 | R+4
Galette - Résa - PVC3:CFO125 P110:3883039 | R+4
Galette - Résa - PVC3:CFO125 P110:3883041 | R+4
Galette - Résa - PVC3:CFO125 P110:3883044 | R+4
Galette - Résa - PVC3:CFO125 P110:3883046 | R+4
Galette - Résa - PVC4:CFO125 P110:3885491 | R+5
Galette - Résa - PVC4:CFO125 P110:3885495 | R+5
Galette - Résa - PVC4:CFO125 P110:3885497 | R+5
Galette - Résa - PVC4:CFO125 P110:3885501 | R+5
Galette - Résa - PVC4:CFO125 P110:3885503 | R+5
Galette - Résa - PVC4:CFO125 P110:3885509 | R+5
Galette - Résa - PVC4:CFO125 P110:3885510 | R+5
Galette - Résa - PVC4:CFO125 P110:3885511 | R+5
Galette - Résa - PVC4:CFO125 P110:3885513 | R+5
Galette - Résa - PVC4:CFO125 P110:3885520 | R+5
Galette - Résa - PVC4:CFO125 P110:3885521 | R+5
Galette - Résa - PVC4:CFO125 P110:3885523 | R+5
Galette - Résa - PVC4:CFO125 P110:3885525 | R+5
Galette - Résa - PVC4:CFO125 P110:3885526 | R+5
Galette - Résa - PVC4:CFO125 P110:3885534 | R+5
Galette - Résa - PVC4:CFO125 P110:3885537 | R+5
Galette - Résa - PVC4:CFO125 P110:3885538 | R+5
Galette - Résa - PVC4:CFO125 P110:3885542 | R+5
Galette - Résa - PVC4:CFO125 P110:3885553 | R+5
Galette - Résa - PVC4:CFO125 P110:3885556 | R+5
Galette - Résa - PVC4:CFO125 P110:3885557 | R+5
Galette - Résa - PVC4:CFO125 P110:3885561 | R+5
Galette - Résa - PVC4:CFO125 P110:3885563 | R+5
Galette - Résa - PVC4:CFO125 P110:3885565 | R+5
Galette - Résa - PVC4:CFO125 P110:3885568 | R+5
Galette - Résa - PVC5:CFO125 P110:3888138 | R+6
Galette - Résa - PVC5:CFO125 P110:3888140 | R+6
Galette - Résa - PVC5:CFO125 P110:3888142 | R+6
Galette - Résa - PVC5:CFO125 P110:3888144 | R+6
Galette - Résa - PVC5:CFO125 P110:3888148 | R+6
Galette - Résa - PVC5:CFO125 P110:3888149 | R+6
Galette - Résa - PVC5:CFO125 P110:3888150 | R+6
Galette - Résa - PVC5:CFO125 P110:3888152 | R+6
Galette - Résa - PVC5:CFO125 P110:3888157 | R+6
Galette - Résa - PVC5:CFO125 P110:3888158 | R+6
Galette - Résa - PVC5:CFO125 P110:3888160 | R+6
Galette - Résa - PVC5:CFO125 P110:3888162 | R+6
Galette - Résa - PVC5:CFO125 P110:3888163 | R+6
Galette - Résa - PVC5:CFO125 P110:3888167 | R+6
Galette - Résa - PVC5:CFO125 P110:3888170 | R+6
Galette - Résa - PVC5:CFO125 P110:3888171 | R+6
Galette - Résa - PVC5:CFO125 P110:3888174 | R+6
Galette - Résa - PVC5:CFO125 P110:3888175 | R+6
Galette - Résa - PVC5:CFO125 P110:3888178 | R+6
Galette - Résa - PVC5:CFO125 P110:3888179 | R+6
Galette - Résa - PVC5:CFO125 P110:3888181 | R+6
Galette - Résa - PVC5:CFO125 P110:3888183 | R+6
Galette - Résa - PVC5:CFO125 P110:3888185 | R+6
Galette - Résa - PVC5:CFO125 P110:3888187 | R+6
Galette - Résa - PVC5:CFO125 P110:3888189 | R+6

# IfcBuildingElementProxy: CFO140 P135 (21)
Type - Material: Conduit VMC
Pset_BuildingElementProxyCommon - Reference: CFO140 P135
Name | In
Galette - Résa - PVC1:CFO140 P135:3861321 | R+2
Galette - Résa - PVC1:CFO140 P135:3861325 | R+2
Galette - Résa - PVC1:CFO140 P135:3861377 | R+2
Galette - Résa - PVC1:CFO140 P135:3861390 | R+2
Galette - Résa - PVC1:CFO140 P135:3861399 | R+2
Galette - Résa - PVC1:CFO140 P135:3861408 | R+2
Galette - Résa - PVC2:CFO140 P135:3880397 | R+3
Galette - Résa - PVC2:CFO140 P135:3880410 | R+3
Galette - Résa - PVC2:CFO140 P135:3880426 | R+3
Galette - Résa - PVC2:CFO140 P135:3880443 | R+3
Galette - Résa - PVC3:CFO140 P135:3882992 | R+4
Galette - Résa - PVC3:CFO140 P135:3883003 | R+4
Galette - Résa - PVC3:CFO140 P135:3883020 | R+4
Galette - Résa - PVC3:CFO140 P135:3883032 | R+4
Galette - Résa - PVC4:CFO140 P135:3885524 | R+5
Galette - Résa - PVC4:CFO140 P135:3885535 | R+5
Galette - Résa - PVC4:CFO140 P135:3885558 | R+5
Galette - Résa - PVC5:CFO140 P135:3888161 | R+6
Galette - Résa - PVC5:CFO140 P135:3888168 | R+6
Galette - Résa - PVC5:CFO140 P135:3888182 | R+6
Galette - Résa - PVC5:CFO140 P135:3888188 | R+6

# IfcBuildingElementProxy: CFO160 P150 (10)
Type - Material: Conduit EP
Pset_BuildingElementProxyCommon - Reference: CFO160 P150
Name | In
Galette - Résa - PVC1:CFO160 P150:3861339 | R+2
Galette - Résa - PVC1:CFO160 P150:3861438 | R+2
Galette - Résa - PVC2:CFO160 P150:3880398 | R+3
Galette - Résa - PVC2:CFO160 P150:3880424 | R+3
Galette - Résa - PVC3:CFO160 P150:3882943 | R+4
Galette - Résa - PVC3:CFO160 P150:3883001 | R+4
Galette - Résa - PVC4:CFO160 P150:3885487 | R+5
Galette - Résa - PVC4:CFO160 P150:3885533 | R+5
Galette - Résa - PVC5:CFO160 P150:3888134 | R+6
Galette - Résa - PVC5:CFO160 P150:3888166 | R+6

# IfcBuildingElementProxy: CFO200 P170 (9)
Type - Material: Conduit VMC
Pset_BuildingElementProxyCommon - Reference: CFO200 P170
Name | In
Galette - Résa - PVC1:CFO200 P170:3861378 | R+2
Galette - Résa - PVC1:CFO200 P170:3861384 | R+2
Galette - Résa - PVC2:CFO200 P170:3880364 | R+3
Galette - Résa - PVC3:CFO200 P170:3882967 | R+4
Galette - Résa - PVC3:CFO200 P170:3882969 | R+4
Galette - Résa - PVC4:CFO200 P170:3885496 | R+5
Galette - Résa - PVC4:CFO200 P170:3885506 | R+5
Galette - Résa - PVC5:CFO200 P170:3888139 | R+6
Galette - Résa - PVC5:CFO200 P170:3888145 | R+6

# IfcBuildingElementProxy: CFO235 P210 (65)
Type - Material: Conduit VMC
Pset_BuildingElementProxyCommon - Reference: CFO235 P210
Name | In
Galette - Résa - PVC1:CFO235 P210:3861318 | R+2
Galette - Résa - PVC1:CFO235 P210:3861320 | R+2
Galette - Résa - PVC1:CFO235 P210:3861324 | R+2
Galette - Résa - PVC1:CFO235 P210:3861344 | R+2
Galette - Résa - PVC1:CFO235 P210:3861346 | R+2
Galette - Résa - PVC1:CFO235 P210:3861389 | R+2
Galette - Résa - PVC1:CFO235 P210:3861391 | R+2
Galette - Résa - PVC1:CFO235 P210:3861392 | R+2
Galette - Résa - PVC1:CFO235 P210:3861400 | R+2
Galette - Résa - PVC1:CFO235 P210:3861404 | R+2
Galette - Résa - PVC1:CFO235 P210:3861405 | R+2
Galette - Résa - PVC1:CFO235 P210:3861413 | R+2
Galette - Résa - PVC1:CFO235 P210:3861428 | R+2
Galette - Résa - PVC1:CFO235 P210:3861437 | R+2
Galette - Résa - PVC2:CFO235 P210:3880355 | R+3
Galette - Résa - PVC2:CFO235 P210:3880365 | R+3
Galette - Résa - PVC2:CFO235 P210:3880366 | R+3
Galette - Résa - PVC2:CFO235 P210:3880371 | R+3
Galette - Résa - PVC2:CFO235 P210:3880386 | R+3
Galette - Résa - PVC2:CFO235 P210:3880388 | R+3
Galette - Résa - PVC2:CFO235 P210:3880389 | R+3
Galette - Résa - PVC2:CFO235 P210:3880390 | R+3
Galette - Résa - PVC2:CFO235 P210:3880395 | R+3
Galette - Résa - PVC2:CFO235 P210:3880407 | R+3
Galette - Résa - PVC2:CFO235 P210:3880415 | R+3
Galette - Résa - PVC2:CFO235 P210:3880432 | R+3
Galette - Résa - PVC2:CFO235 P210:3880433 | R+3
Galette - Résa - PVC2:CFO235 P210:3880451 | R+3
Galette - Résa - PVC3:CFO235 P210:3882959 | R+4
Galette - Résa - PVC3:CFO235 P210:3882970 | R+4
Galette - Résa - PVC3:CFO235 P210:3882971 | R+4
Galette - Résa - PVC3:CFO235 P210:3882975 | R+4
Galette - Résa - PVC3:CFO235 P210:3882984 | R+4
Galette - Résa - PVC3:CFO235 P210:3882990 | R+4
Galette - Résa - PVC3:CFO235 P210:3883004 | R+4
Galette - Résa - PVC3:CFO235 P210:3883010 | R+4
Galette - Résa - PVC3:CFO235 P210:3883026 | R+4
Galette - Résa - PVC3:CFO235 P210:3883027 | R+4
Galette - Résa - PVC3:CFO235 P210:3883045 | R+4
Galette - Résa - PVC3:CFO235 P210:3883047 | R+4
Galette - Résa - PVC3:CFO235 P210:3883048 | R+4
Galette - Résa - PVC4:CFO235 P210:3885466 | R+5
Galette - Résa - PVC4:CFO235 P210:3885498 | R+5
Galette - Résa - PVC4:CFO235 P210:3885507 | R+5
Galette - Résa - PVC4:CFO235 P210:3885508 | R+5
Galette - Résa - PVC4:CFO235 P210:3885512 | R+5
Galette - Résa - PVC4:CFO235 P210:3885522 | R+5
Galette - Résa - PVC4:CFO235 P210:3885536 | R+5
Galette - Résa - PVC4:CFO235 P210:3885554 | R+5
Galette - Résa - PVC4:CFO235 P210:3885555 | R+5
Galette - Résa - PVC4:CFO235 P210:3885569 | R+5
Galette - Résa - PVC4:CFO235 P210:3885570 | R+5
Galette - Résa - PVC4:CFO235 P210:3885571 | R+5
Galette - Résa - PVC5:CFO235 P210:3888141 | R+6
Galette - Résa - PVC5:CFO235 P210:3888146 | R+6
Galette - Résa - PVC5:CFO235 P210:3888147 | R+6
Galette - Résa - PVC5:CFO235 P210:3888151 | R+6
Galette - Résa - PVC5:CFO235 P210:3888159 | R+6
Galette - Résa - PVC5:CFO235 P210:3888169 | R+6
Galette - Résa - PVC5:CFO235 P210:3888173 | R+6
Galette - Résa - PVC5:CFO235 P210:3888177 | R+6
Galette - Résa - PVC5:CFO235 P210:3888184 | R+6
Galette - Résa - PVC5:CFO235 P210:3888190 | R+6
Galette - Résa - PVC5:CFO235 P210:3888191 | R+6
Galette - Résa - PVC5:CFO235 P210:3888192 | R+6

# IfcBuildingElementProxy: CFO285 P260 (45)
Type - Material: Conduit VMC
Pset_BuildingElementProxyCommon - Reference: CFO285 P260
Name | In
Galette - Résa - PVC1:CFO285 P260:3861342 | R+2
Galette - Résa - PVC1:CFO285 P260:3861382 | R+2
Galette - Résa - PVC1:CFO285 P260:3861385 | R+2
Galette - Résa - PVC1:CFO285 P260:3861388 | R+2
Galette - Résa - PVC1:CFO285 P260:3861397 | R+2
Galette - Résa - PVC1:CFO285 P260:3861398 | R+2
Galette - Résa - PVC1:CFO285 P260:3861403 | R+2
Galette - Résa - PVC1:CFO285 P260:3861407 | R+2
Galette - Résa - PVC2:CFO285 P260:3880359 | R+3
Galette - Résa - PVC2:CFO285 P260:3880375 | R+3
Galette - Résa - PVC2:CFO285 P260:3880378 | R+3
Galette - Résa - PVC2:CFO285 P260:3880405 | R+3
Galette - Résa - PVC2:CFO285 P260:3880406 | R+3
Galette - Résa - PVC2:CFO285 P260:3880412 | R+3
Galette - Résa - PVC2:CFO285 P260:3880430 | R+3
Galette - Résa - PVC2:CFO285 P260:3880438 | R+3
Galette - Résa - PVC2:CFO285 P260:3880446 | R+3
Galette - Résa - PVC3:CFO285 P260:3882963 | R+4
Galette - Résa - PVC3:CFO285 P260:3882977 | R+4
Galette - Résa - PVC3:CFO285 P260:3882981 | R+4
Galette - Résa - PVC3:CFO285 P260:3882985 | R+4
Galette - Résa - PVC3:CFO285 P260:3882999 | R+4
Galette - Résa - PVC3:CFO285 P260:3883000 | R+4
Galette - Résa - PVC3:CFO285 P260:3883007 | R+4
Galette - Résa - PVC3:CFO285 P260:3883024 | R+4
Galette - Résa - PVC3:CFO285 P260:3883033 | R+4
Galette - Résa - PVC3:CFO285 P260:3883040 | R+4
Galette - Résa - PVC4:CFO285 P260:3885502 | R+5
Galette - Résa - PVC4:CFO285 P260:3885514 | R+5
Galette - Résa - PVC4:CFO285 P260:3885517 | R+5
Galette - Résa - PVC4:CFO285 P260:3885531 | R+5
Galette - Résa - PVC4:CFO285 P260:3885532 | R+5
Galette - Résa - PVC4:CFO285 P260:3885539 | R+5
Galette - Résa - PVC4:CFO285 P260:3885550 | R+5
Galette - Résa - PVC4:CFO285 P260:3885562 | R+5
Galette - Résa - PVC4:CFO285 P260:3885564 | R+5
Galette - Résa - PVC5:CFO285 P260:3888143 | R+6
Galette - Résa - PVC5:CFO285 P260:3888153 | R+6
Galette - Résa - PVC5:CFO285 P260:3888156 | R+6
Galette - Résa - PVC5:CFO285 P260:3888164 | R+6
Galette - Résa - PVC5:CFO285 P260:3888165 | R+6
Galette - Résa - PVC5:CFO285 P260:3888172 | R+6
Galette - Résa - PVC5:CFO285 P260:3888176 | R+6
Galette - Résa - PVC5:CFO285 P260:3888180 | R+6
Galette - Résa - PVC5:CFO285 P260:3888186 | R+6

# IfcBuildingElementProxy: CHF Aller 40 (3)
In: R+1
Type - Material: Circuit CHF Aller
Pset_BuildingElementProxyCommon - Reference: CHF Aller 40
Name (Galette - Résa - PVC:CHF Aller 40:...)
3841184
3841188
3841189

# IfcBuildingElementProxy: CHF Aller 41 (12)
Type - Material: Circuit CHF Aller
Pset_BuildingElementProxyCommon - Reference: CHF Aller 41
Name | In
Galette - Résa - PVC1:CHF Aller 41:3861350 | R+2
Galette - Résa - PVC1:CHF Aller 41:3861414 | R+2
Galette - Résa - PVC1:CHF Aller 41:3861419 | R+2
Galette - Résa - PVC2:CHF Aller 41:3880382 | R+3
Galette - Résa - PVC2:CHF Aller 41:3880419 | R+3
Galette - Résa - PVC2:CHF Aller 41:3880422 | R+3
Galette - Résa - PVC3:CHF Aller 41:3882956 | R+4
Galette - Résa - PVC3:CHF Aller 41:3883014 | R+4
Galette - Résa - PVC3:CHF Aller 41:3883016 | R+4
Galette - Résa - PVC4:CHF Aller 41:3885493 | R+5
Galette - Résa - PVC4:CHF Aller 41:3885545 | R+5
Galette - Résa - PVC4:CHF Aller 41:3885547 | R+5

# IfcBuildingElementProxy: CHF Retour 42 (2)
In: R+1
Type - Material: Circuit CHF Retour
Pset_BuildingElementProxyCommon - Reference: CHF Retour 42
Name (Galette - Résa - PVC:CHF Retour 42:...)
3841185
3841187

# IfcBuildingElementProxy: CHF Retour 43 (12)
Type - Material: Circuit CHF Retour
Pset_BuildingElementProxyCommon - Reference: CHF Retour 43
Name | In
Galette - Résa - PVC1:CHF Retour 43:3861351 | R+2
Galette - Résa - PVC1:CHF Retour 43:3861415 | R+2
Galette - Résa - PVC1:CHF Retour 43:3861418 | R+2
Galette - Résa - PVC2:CHF Retour 43:3880383 | R+3
Galette - Résa - PVC2:CHF Retour 43:3880418 | R+3
Galette - Résa - PVC2:CHF Retour 43:3880423 | R+3
Galette - Résa - PVC3:CHF Retour 43:3882957 | R+4
Galette - Résa - PVC3:CHF Retour 43:3883013 | R+4
Galette - Résa - PVC3:CHF Retour 43:3883017 | R+4
Galette - Résa - PVC4:CHF Retour 43:3885494 | R+5
Galette - Résa - PVC4:CHF Retour 43:3885544 | R+5
Galette - Résa - PVC4:CHF Retour 43:3885548 | R+5

# IfcBuildingElementProxy: Décaissé (44)
Type - Material: BBGO_Résa
Pset_BuildingElementProxyCommon - Reference: Décaissé
Name | In
Décaissé:Décaissé:3104507 | R+1
Décaissé1:Décaissé:3106316 | R+1
Décaissé2:Décaissé:3107210 | R+1
Décaissé3:Décaissé:3108276 | R+1
Décaissé5:Décaissé:3110494 | R+1
Décaissé7:Décaissé:3111701 | R+1
Décaissé8:Décaissé:3111850 | R+1
Décaissé9:Décaissé:3112291 | R+1
Décaissé10:Décaissé:3112987 | R+1
Décaissé11:Décaissé:3113794 | R+1
Décaissé13:Décaissé:3150272 | R+2
Décaissé15:Décaissé:3150297 | R+2
Décaissé16:Décaissé:3150313 | R+2
Décaissé18:Décaissé:3150343 | R+2
Décaissé20:Décaissé:3150371 | R+2
Décaissé21:Décaissé:3150385 | R+2
Décaissé22:Décaissé:3150399 | R+2
Décaissé23:Décaissé:3150415 | R+2
Décaissé24:Décaissé:3150433 | R+2
Décaissé29:Décaissé:3152489 | R+3
Décaissé30:Décaissé:3152505 | R+3
Décaissé31:Décaissé:3152519 | R+3
Décaissé33:Décaissé:3152547 | R+3
Décaissé34:Décaissé:3152561 | R+3
Décaissé35:Décaissé:3152575 | R+3
Décaissé32:Décaissé:3154555 | R+3
Décaissé51:Décaissé:3156489 | R+5
Décaissé53:Décaissé:3156517 | R+5
Décaissé54:Décaissé:3156533 | R+5
Décaissé55:Décaissé:3156547 | R+5
Décaissé56:Décaissé:3156561 | R+5
Décaissé59:Décaissé:3156605 | R+5
Décaissé61:Décaissé:3156691 | R+5
Décaissé4:Décaissé:3746558 | R+3
Décaissé6:Décaissé:3746645 | R+4
Décaissé12:Décaissé:3747478 | R+3
Décaissé14:Décaissé:3750471 | R+4
Décaissé17:Décaissé:3750503 | R+4
Décaissé19:Décaissé:3750618 | R+4
Décaissé25:Décaissé:3750632 | R+4
Décaissé26:Décaissé:3750743 | R+4
Décaissé27:Décaissé:3750770 | R+4
Décaissé28:Décaissé:3750938 | R+4
Décaissé36:Décaissé:3750952 | R+4

# IfcBuildingElementProxy: ECS Aller 32 (12)
In: R+1
Type - Material: Circuit ECS Aller
Pset_BuildingElementProxyCommon - Reference: ECS Aller 32
Name (Galette - Résa - PVC:ECS Aller 32:...)
3841194
3841196
3841198
3841200
3841203
3841205
3841207
3841209
3841211
3841214
3841215
3841217

# IfcBuildingElementProxy: ECS Retour 20 (12)
In: R+1
Type - Material: Circuit ECS Retour
Pset_BuildingElementProxyCommon - Reference: ECS Retour 20
Name (Galette - Résa - PVC:ECS Retour 20:...)
3841195
3841197
3841199
3841201
3841204
3841206
3841208
3841210
3841212
3841213
3841216
3841218

# IfcBuildingElementProxy: EF 40 (3)
In: R+1
Type - Material: Circuit EF
Pset_BuildingElementProxyCommon - Reference: EF 40
Name (Galette - Résa - PVC:EF 40:...)
3841182
3841183
3841186

# IfcBuildingElementProxy: EF 41 (8)
Type - Material: Circuit EF
Pset_BuildingElementProxyCommon - Reference: EF 41
Name | In
Galette - Résa - PVC1:EF 41:3861429 | R+2
Galette - Résa - PVC1:EF 41:3861430 | R+2
Galette - Résa - PVC2:EF 41:3880420 | R+3
Galette - Résa - PVC2:EF 41:3880453 | R+3
Galette - Résa - PVC3:EF 41:3883015 | R+4
Galette - Résa - PVC3:EF 41:3883018 | R+4
Galette - Résa - PVC4:EF 41:3885546 | R+5
Galette - Résa - PVC4:EF 41:3885549 | R+5

# IfcBuildingElementProxy: EF 50 (4)
Type - Material: Circuit EF
Pset_BuildingElementProxyCommon - Reference: EF 50
Name | In
Galette - Résa - PVC1:EF 50:3861376 | R+2
Galette - Résa - PVC2:EF 50:3880384 | R+3
Galette - Résa - PVC3:EF 50:3882955 | R+4
Galette - Résa - PVC4:EF 50:3885492 | R+5

# IfcBuildingElementProxy: EP 100 (32)
In: R+1
Type - Material: Conduit EP
Pset_BuildingElementProxyCommon - Reference: EP 100
Name (Galette - Résa - PVC:EP 100:...)
3841110
3841112
3841113
3841114
3841115
3841116
3841117
3841118
3841119
3841120
3841123
3841124
3841125
3841126
3841127
3841128
3841129
3841130
3841131
3841144
3841145
3841146
3841147
3841148
3841152
3841153
3841154
3841155
3841156
3841157
3841180
3841222

# IfcBuildingElementProxy: EP 101 (40)
Type - Material: Conduit EP
Pset_BuildingElementProxyCommon - Reference: EP 101
Name | In
Galette - Résa - PVC1:EP 101:3861326 | R+2
Galette - Résa - PVC1:EP 101:3861327 | R+2
Galette - Résa - PVC1:EP 101:3861328 | R+2
Galette - Résa - PVC1:EP 101:3861329 | R+2
Galette - Résa - PVC1:EP 101:3861330 | R+2
Galette - Résa - PVC1:EP 101:3861331 | R+2
Galette - Résa - PVC1:EP 101:3861332 | R+2
Galette - Résa - PVC1:EP 101:3861333 | R+2
Galette - Résa - PVC1:EP 101:3861334 | R+2
Galette - Résa - PVC1:EP 101:3861335 | R+2
Galette - Résa - PVC1:EP 101:3861336 | R+2
Galette - Résa - PVC1:EP 101:3861337 | R+2
Galette - Résa - PVC1:EP 101:3861343 | R+2
Galette - Résa - PVC2:EP 101:3880452 | R+3
Galette - Résa - PVC3:EP 101:3882946 | R+4
Galette - Résa - PVC3:EP 101:3882947 | R+4
Galette - Résa - PVC3:EP 101:3882948 | R+4
Galette - Résa - PVC3:EP 101:3882949 | R+4
Galette - Résa - PVC3:EP 101:3882950 | R+4
Galette - Résa - PVC3:EP 101:3882951 | R+4
Galette - Résa - PVC3:EP 101:3882952 | R+4
Galette - Résa - PVC3:EP 101:3882953 | R+4
Galette - Résa - PVC3:EP 101:3882954 | R+4
Galette - Résa - PVC4:EP 101:3885469 | R+5
Galette - Résa - PVC4:EP 101:3885470 | R+5
Galette - Résa - PVC4:EP 101:3885471 | R+5
Galette - Résa - PVC4:EP 101:3885472 | R+5
Galette - Résa - PVC4:EP 101:3885473 | R+5
Galette - Résa - PVC4:EP 101:3885474 | R+5
Galette - Résa - PVC4:EP 101:3885475 | R+5
Galette - Résa - PVC4:EP 101:3885476 | R+5
Galette - Résa - PVC4:EP 101:3885477 | R+5
Galette - Résa - PVC4:EP 101:3885478 | R+5
Galette - Résa - PVC4:EP 101:3885479 | R+5
Galette - Résa - PVC4:EP 101:3885480 | R+5
Galette - Résa - PVC4:EP 101:3885481 | R+5
Galette - Résa - PVC4:EP 101:3885482 | R+5
Galette - Résa - PVC4:EP 101:3885483 | R+5
Galette - Résa - PVC4:EP 101:3885484 | R+5
Galette - Résa - PVC4:EP 101:3885485 | R+5

# IfcBuildingElementProxy: EP 110 (2)
In: R+1
Type - Material: Conduit EP
Pset_BuildingElementProxyCommon - Reference: EP 110
Name (Galette - Résa - PVC:EP 110:...)
3841111
3841132

# IfcBuildingElementProxy: EP 125 (2)
In: R+1
Type - Material: Conduit EP
Pset_BuildingElementProxyCommon - Reference: EP 125
Name (Galette - Résa - PVC:EP 125:...)
3841134
3841221

# IfcBuildingElementProxy: EP 126 (7)
Type - Material: Conduit EP
Pset_BuildingElementProxyCommon - Reference: EP 126
Name | In
Galette - Résa - PVC1:EP 126:3861341 | R+2
Galette - Résa - PVC2:EP 126:3880381 | R+3
Galette - Résa - PVC3:EP 126:3882945 | R+4
Galette - Résa - PVC4:EP 126:3885488 | R+5
Galette - Résa - PVC4:EP 126:3885489 | R+5
Galette - Résa - PVC5:EP 126:3888136 | R+6
Galette - Résa - PVC5:EP 126:3888137 | R+6

# IfcBuildingElementProxy: EP 140 (3)
In: R+1
Type - Material: Conduit EP
Pset_BuildingElementProxyCommon - Reference: EP 140
Name (Galette - Résa - PVC:EP 140:...)
3841121
3841150
3841151

# IfcBuildingElementProxy: EP 141 (3)
Type - Material: Conduit EP
Pset_BuildingElementProxyCommon - Reference: EP 141
Name | In
Galette - Résa - PVC4:EP 141:3885486 | R+5
Galette - Résa - PVC5:EP 141:3888133 | R+6
Galette - Résa - PVC5:EP 141:3888135 | R+6

# IfcBuildingElementProxy: EP 160, Galette - Résa - PVC:EP 160:3841149
In: R+1
Type - Material: Conduit EP
Pset_BuildingElementProxyCommon - Reference: EP 160

# IfcBuildingElementProxy: EP 161 (10)
Type - Material: Conduit EP
Pset_BuildingElementProxyCommon - Reference: EP 161
Name | In
Galette - Résa - PVC1:EP 161:3861338 | R+2
Galette - Résa - PVC1:EP 161:3861340 | R+2
Galette - Résa - PVC1:EP 161:3861417 | R+2
Galette - Résa - PVC2:EP 161:3880380 | R+3
Galette - Résa - PVC2:EP 161:3880417 | R+3
Galette - Résa - PVC2:EP 161:3880421 | R+3
Galette - Résa - PVC3:EP 161:3882942 | R+4
Galette - Résa - PVC3:EP 161:3882944 | R+4
Galette - Résa - PVC3:EP 161:3883012 | R+4
Galette - Résa - PVC4:EP 161:3885543 | R+5

# IfcBuildingElementProxy: EU 100 (33)
In: R+1
Type - Material: Conduit EU
Pset_BuildingElementProxyCommon - Reference: EU 100
Name (Galette - Résa - PVC:EU 100:...)
3841095
3841096
3841098
3841099
3841100
3841101
3841102
3841103
3841104
3841105
3841106
3841133
3841135
3841136
3841138
3841161
3841167
3841168
3841169
3841170
3841171
3841172
3841173
3841174
3841175
3841176
3841177
3841178
3841179
3841191
3841192
3841193
3841202

# IfcBuildingElementProxy: EU 110 (2)
Type - Material: Conduit EU
Pset_BuildingElementProxyCommon - Reference: EU 110
Name | In
Galette - Résa - PVC4:EU 110:3885467 | R+5
Galette - Résa - PVC5:EU 110:3888154 | R+6

# IfcBuildingElementProxy: EU 40, Galette - Résa - PVC:EU 40:3841097
In: R+1
Type - Material: Conduit EU
Pset_BuildingElementProxyCommon - Reference: EU 40

# IfcBuildingElementProxy: EU 50 (19)
In: R+1
Type - Material: Conduit EU
Pset_BuildingElementProxyCommon - Reference: EU 50
Name (Galette - Résa - PVC:EU 50:...)
3841107
3841108
3841109
3841122
3841139
3841140
3841141
3841142
3841143
3841159
3841160
3841162
3841163
3841164
3841165
3841166
3841219
3841220
3841223

# IfcBuildingElementProxy: EU 51 (2)
In: R+2
Type - Material: Conduit EU
Pset_BuildingElementProxyCommon - Reference: EU 51
Name (Galette - Résa - PVC1:EU 51:...)
3861416
3861420

# IfcBuildingElementProxy: J.F. (62)
Type - Material: BBGO_Résa
Pset_BuildingElementProxyCommon - Reference: J.F.
Name (BBGO-Résa rect et circ:J.F.:...) | In
2016946 | R+6
2018367 | R+6
2018391 | R+6
2018415 | R+6
2018441 | R+6
2018465 | R+6
2018493 | R+6
2018521 | R+6
2018547 | R+6
2018575 | R+6
2018609 | R+6
2018752 | R+6
2018776 | R+6
2018802 | R+6
2018826 | R+6
2018848 | R+6
2018878 | R+6
2019505 | R+6
2019529 | R+6
2019561 | R+6
2019637 | R+6
2019673 | R+6
2019701 | R+6
2019725 | R+6
2019751 | R+6
2019800 | R+6
2019870 | R+6
2019892 | R+6
2019918 | R+6
2019940 | R+6
2019966 | R+6
2020074 | R+6
2020138 | R+6
2020162 | R+6
2020184 | R+6
2020210 | R+6
2020277 | R+6
2020320 | R+6
2020390 | R+6
2020447 | R+6
2350318 | R+5
2350497 | R+5
2350827 | R+5
2350905 | R+5
2350974 | R+5
2351330 | R+5
2351359 | R+5
2351463 | R+5
2351539 | R+5
2351568 | R+5
2351597 | R+5
2351663 | R+5
2351775 | R+5
2351846 | R+5
2351906 | R+5
2351937 | R+5
2352072 | R+5
2352101 | R+5
3912179 | R+5
4001429 | R+5
4001739 | R+5
4001811 | R+5

# IfcBuildingElementProxy: Lg34C, Lg34C:Lg34C:2400810
In: ±0.00
Type - Material: Béton, C25/30
Pset_BuildingElementProxyCommon - Reference: Lg34C

# IfcBuildingElementProxy: Lg79C', Lg79C':Lg79C':3189633
In: ±0.00
Type - Material: Béton, C25/30
Pset_BuildingElementProxyCommon - Reference: Lg79C'

# IfcBuildingElementProxy: Ossature 1 (2)
In: ±0.00
Type - Material: Béton, C25/30
Pset_BuildingElementProxyCommon - Reference: Ossature 1
Name
Ossature 1:Ossature 1:1696335
Ossature 2:Ossature 1:1778586

# IfcBuildingElementProxy: Réservation (25)
Type - Material: BBGO_Résa
Pset_BuildingElementProxyCommon - Reference: Réservation
Name (BBGO-Résa rect et circ:Réservation:...) | In
1996338 | +3.61
2006150 | +3.61
2006355 | +3.66
2007021 | +3.66
2007249 | +3.74
2007357 | +3.74
2020741 | +3.61
2021178 | +3.53
2021911 | +3.74
2022371 | +3.74
2022736 | +3.74
2023335 | R+6
2024101 | R+6
2024129 | R+6
2042733 | +3.74
2043988 | +3.66
2044765 | +3.45
2045312 | +3.45
2045364 | +3.66
2473270 | +3.77
2958695 | +3.66
3330852 | +3.69
3334090 | +3.45
3480112 | +3.77
3486429 | +3.77

# IfcBuildingElementProxy: Siphon de balcon (37)
Type - Material: BBGO_Résa
Pset_BuildingElementProxyCommon - Reference: Siphon de balcon
Name | In
Siphon de balcon:Siphon de balcon:3580393 | ±0.00
Siphon de balcon1:Siphon de balcon:3582940 | ±0.00
Siphon de balcon2:Siphon de balcon:3583350 | ±0.00
Siphon de balcon3:Siphon de balcon:3583376 | ±0.00
Siphon de balcon4:Siphon de balcon:3583497 | ±0.00
Siphon de balcon5:Siphon de balcon:3583674 | ±0.00
Siphon de balcon6:Siphon de balcon:3583753 | ±0.00
Siphon de balcon7:Siphon de balcon:3583779 | ±0.00
Siphon de balcon8:Siphon de balcon:3583805 | ±0.00
Siphon de balcon9:Siphon de balcon:3583831 | ±0.00
Siphon de balcon10:Siphon de balcon:3583857 | ±0.00
Siphon de balcon11:Siphon de balcon:3583883 | ±0.00
Siphon de balcon12:Siphon de balcon:3584984 | ±0.00
Siphon de balcon13:Siphon de balcon:3585010 | ±0.00
Siphon de balcon14:Siphon de balcon:3585036 | ±0.00
Siphon de balcon15:Siphon de balcon:3585062 | ±0.00
Siphon de balcon16:Siphon de balcon:3585260 | ±0.00
Siphon de balcon17:Siphon de balcon:3585396 | ±0.00
Siphon de balcon18:Siphon de balcon:3585415 | ±0.00
Siphon de balcon19:Siphon de balcon:3585434 | ±0.00
Siphon de balcon20:Siphon de balcon:3585925 | ±0.00
Siphon de balcon21:Siphon de balcon:3586032 | ±0.00
Siphon de balcon22:Siphon de balcon:3586051 | ±0.00
Siphon de balcon23:Siphon de balcon:3586070 | ±0.00
Siphon de balcon27:Siphon de balcon:3594272 | ±0.00
Siphon de balcon26:Siphon de balcon:3594492 | ±0.00
Siphon de balcon25:Siphon de balcon:3594513 | ±0.00
Siphon de balcon24:Siphon de balcon:3594534 | ±0.00
Siphon de balcon28:Siphon de balcon:3603715 | Ac R+1
Siphon de balcon29:Siphon de balcon:3611578 | Ac R+1
Siphon de balcon30:Siphon de balcon:3612680 | Ac R+2
Siphon de balcon31:Siphon de balcon:3612699 | Ac R+2
Siphon de balcon32:Siphon de balcon:3674017 | Ac R+1
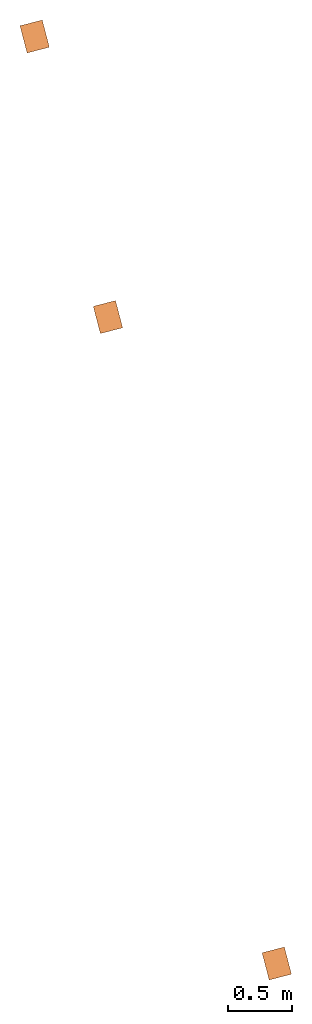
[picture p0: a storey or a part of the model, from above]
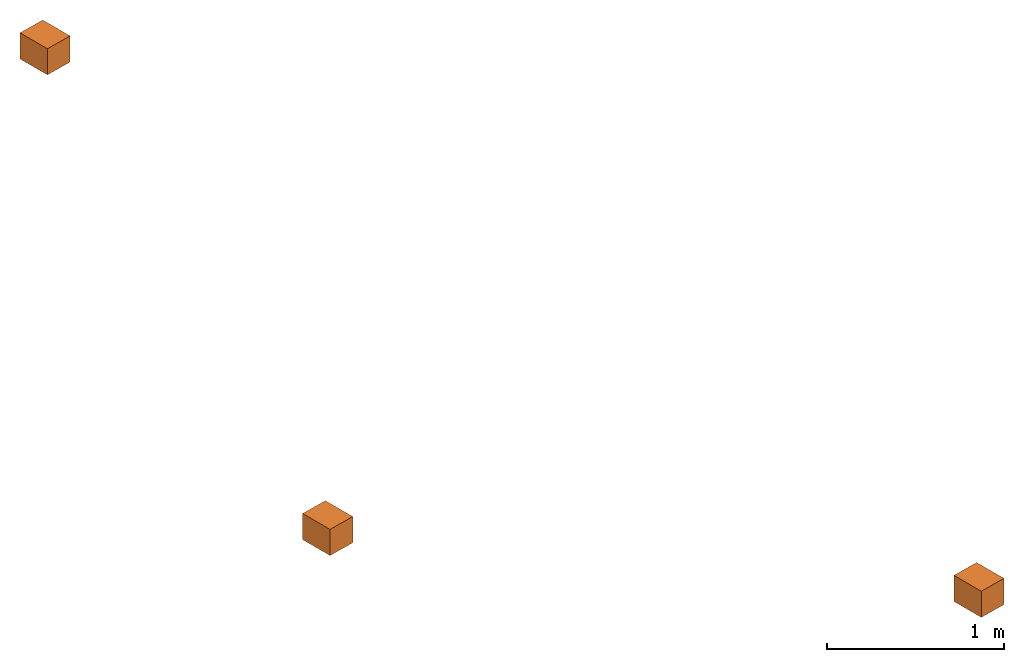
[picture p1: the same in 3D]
Properties of the parts of a building model (IFC2X3), part 2 of 2

# IfcBuildingElementProxy: Siphon de balcon (37)
Name | In
Siphon de balcon33:Siphon de balcon:3681478 | Ac R+2
Siphon de balcon34:Siphon de balcon:3681499 | Ac R+3
Siphon de balcon35:Siphon de balcon:3681516 | Ac R+3
Siphon de balcon36:Siphon de balcon:3681533 | Ac R+3

# IfcBuildingElementProxy: Standard (7)
In: RDC
Pset_BuildingElementProxyCommon - Reference: Standard
Name
RESERVATION CIRC_MUR2:Standard:3360114
RESERVATION CIRC_MUR2:Standard:3360115
RESERVATION RECT_MUR1:Standard:3360116
RESERVATION CIRC_MUR2:Standard:3364436
RESERVATION CIRC_MUR2:Standard:3364461
RESERVATION CIRC_MUR2:Standard:3972531
RESERVATION CIRC_MUR2:Standard:3972612

# IfcBuildingElementProxy: Standard (125)
Type - Material: Verre
Pset_BuildingElementProxyCommon - Reference: Standard
Name | In
RESERVATION CIRC_MUR:Standard:2367435 | RDC
RESERVATION CIRC_MUR:Standard:2367436 | RDC
RESERVATION CIRC_MUR:Standard:2367437 | RDC
RESERVATION CIRC_MUR:Standard:2367438 | RDC
RESERVATION CIRC_MUR:Standard:2367439 | RDC
RESERVATION CIRC_MUR:Standard:2367440 | RDC
RESERVATION CIRC_MUR:Standard:2367441 | RDC
RESERVATION CIRC_MUR:Standard:2367442 | RDC
RESERVATION CIRC_MUR:Standard:2367446 | RDC
RESERVATION CIRC_MUR:Standard:2367447 | RDC
RESERVATION CIRC_MUR:Standard:2367449 | RDC
RESERVATION CIRC_MUR:Standard:2367451 | RDC
RESERVATION CIRC_MUR:Standard:2367452 | RDC
RESERVATION CIRC_MUR:Standard:2367454 | RDC
BBGO_Résa_Circ:Standard:2367455 | RDC
RESERVATION CIRC_MUR:Standard:2367456 | RDC
RESERVATION CIRC_MUR:Standard:2367458 | RDC
RESERVATION CIRC_MUR:Standard:2367459 | RDC
RESERVATION CIRC_MUR:Standard:2367460 | RDC
RESERVATION CIRC_MUR:Standard:2367462 | RDC
RESERVATION CIRC_MUR:Standard:2367463 | RDC
RESERVATION CIRC_MUR:Standard:2367464 | RDC
RESERVATION CIRC_MUR:Standard:2367465 | RDC
RESERVATION CIRC_MUR:Standard:2367466 | RDC
RESERVATION CIRC_MUR:Standard:2367467 | RDC
RESERVATION CIRC_MUR:Standard:2367468 | RDC
RESERVATION CIRC_MUR:Standard:2367469 | RDC
RESERVATION CIRC_MUR:Standard:2367470 | RDC
RESERVATION CIRC_MUR:Standard:2367471 | RDC
RESERVATION CIRC_MUR:Standard:2367473 | RDC
RESERVATION CIRC_MUR:Standard:2395577 | RDC
RESERVATION CIRC_MUR:Standard:3247157 | RDC
RESERVATION CIRC_MUR:Standard:3254647 | RDC
RESERVATION CIRC_MUR1:Standard:3254648 | RDC
RESERVATION CIRC_MUR1:Standard:3254649 | RDC
RESERVATION CIRC_MUR1:Standard:3254650 | RDC
RESERVATION CIRC_MUR1:Standard:3254652 | RDC
RESERVATION CIRC_MUR:Standard:3254659 | RDC
RESERVATION CIRC_MUR1:Standard:3254661 | RDC
RESERVATION CIRC_MUR1:Standard:3254662 | RDC
RESERVATION CIRC_MUR1:Standard:3254664 | RDC
RESERVATION CIRC_MUR1:Standard:3254666 | RDC
RESERVATION CIRC_MUR1:Standard:3254668 | RDC
RESERVATION CIRC_MUR1:Standard:3254669 | RDC
RESERVATION CIRC_MUR1:Standard:3254672 | RDC
RESERVATION CIRC_MUR1:Standard:3254674 | RDC
RESERVATION CIRC_MUR1:Standard:3254675 | RDC
RESERVATION CIRC_MUR1:Standard:3254676 | RDC
RESERVATION RECT_MUR:Standard:3254677 | RDC
RESERVATION CIRC_MUR:Standard:3254679 | RDC
RESERVATION CIRC_MUR:Standard:3254680 | RDC
RESERVATION CIRC_MUR1:Standard:3254681 | RDC
RESERVATION CIRC_MUR1:Standard:3254682 | RDC
RESERVATION CIRC_MUR1:Standard:3254683 | RDC
RESERVATION CIRC_MUR1:Standard:3254684 | RDC
RESERVATION CIRC_MUR1:Standard:3254685 | RDC
RESERVATION CIRC_MUR1:Standard:3254686 | RDC
RESERVATION CIRC_MUR1:Standard:3254687 | RDC
RESERVATION RECT_MUR:Standard:3254688 | RDC
RESERVATION RECT_MUR:Standard:3254689 | RDC
RESERVATION RECT_MUR:Standard:3254690 | RDC
RESERVATION RECT_MUR:Standard:3254691 | RDC
RESERVATION RECT_MUR:Standard:3254692 | RDC
RESERVATION RECT_MUR:Standard:3254693 | RDC
RESERVATION RECT_MUR:Standard:3254694 | RDC
RESERVATION RECT_MUR:Standard:3254695 | RDC
RESERVATION RECT_MUR:Standard:3254696 | RDC
RESERVATION RECT_MUR:Standard:3254697 | RDC
RESERVATION RECT_MUR:Standard:3254698 | RDC
RESERVATION RECT_MUR:Standard:3254699 | RDC
RESERVATION RECT_MUR:Standard:3254700 | RDC
RESERVATION RECT_MUR:Standard:3254701 | RDC
RESERVATION RECT_MUR:Standard:3254702 | RDC
RESERVATION RECT_MUR:Standard:3254703 | RDC
RESERVATION RECT_MUR:Standard:3254704 | RDC
RESERVATION RECT_MUR:Standard:3254705 | RDC
RESERVATION RECT_MUR:Standard:3254706 | RDC
RESERVATION RECT_MUR:Standard:3254709 | RDC
RESERVATION RECT_MUR:Standard:3254710 | RDC
RESERVATION RECT_MUR:Standard:3254711 | RDC
RESERVATION RECT_MUR:Standard:3254712 | RDC
RESERVATION RECT_MUR:Standard:3254713 | RDC
RESERVATION CIRC_MUR1:Standard:3254714 | RDC
RESERVATION CIRC_MUR1:Standard:3254715 | RDC
RESERVATION RECT_MUR:Standard:3254716 | RDC
RESERVATION RECT_MUR:Standard:3254717 | RDC
RESERVATION RECT_MUR:Standard:3254718 | RDC
RESERVATION RECT_MUR:Standard:3254719 | RDC
RESERVATION RECT_MUR:Standard:3254720 | RDC
RESERVATION RECT_MUR:Standard:3254721 | RDC
RESERVATION RECT_MUR:Standard:3254722 | RDC
RESERVATION RECT_MUR:Standard:3254723 | RDC
RESERVATION RECT_MUR:Standard:3254724 | RDC
RESERVATION RECT_MUR:Standard:3254725 | RDC
RESERVATION CIRC_MUR1:Standard:3254726 | RDC
RESERVATION CIRC_MUR1:Standard:3254727 | RDC
RESERVATION CIRC_MUR1:Standard:3254728 | RDC
RESERVATION CIRC_MUR1:Standard:3254729 | RDC
RESERVATION CIRC_MUR1:Standard:3254730 | RDC
RESERVATION RECT_MUR:Standard:3254785 | RDC
RESERVATION CIRC_MUR1:Standard:3254791 | RDC
RESERVATION CIRC_MUR1:Standard:3254793 | RDC
RESERVATION CIRC_MUR1:Standard:3254795 | RDC
RESERVATION RECT_MUR:Standard:3254797 | RDC
RESERVATION RECT_MUR:Standard:3254798 | RDC
RESERVATION CIRC_MUR1:Standard:3254802 | RDC
RESERVATION CIRC_MUR:Standard:3374268 | R+1
RESERVATION CIRC_MUR:Standard:3632870 | RDC
RESERVATION CIRC_MUR1:Standard:3633090 | RDC
RESERVATION CIRC_MUR1:Standard:3634484 | RDC
RESERVATION RECT_MUR:Standard:3636256 | RDC
RESERVATION RECT_MUR:Standard:3638937 | RDC
RESERVATION CIRC_MUR:Standard:3639540 | R+1
RESERVATION CIRC_MUR1:Standard:3641116 | RDC
RESERVATION RECT_MUR:Standard:3641417 | RDC
RESERVATION CIRC_MUR:Standard:3755534 | RDC
RESERVATION CIRC_MUR:Standard:3755980 | RDC
RESERVATION CIRC_MUR:Standard:3756342 | RDC
RESERVATION CIRC_MUR:Standard:3757088 | RDC
RESERVATION CIRC_MUR:Standard:3757264 | RDC
RESERVATION CIRC_MUR:Standard:3757437 | RDC
RESERVATION CIRC_MUR:Standard:3757536 | RDC
RESERVATION CIRC_MUR:Standard:3757615 | RDC
RESERVATION CIRC_MUR:Standard:3757822 | RDC
RESERVATION CIRC_MUR:Standard:3757996 | RDC

# IfcBuildingElementProxy: VMC 160, Galette - Résa - PVC:VMC 160:3841181
In: R+1
Type - Material: Conduit VMC
Pset_BuildingElementProxyCommon - Reference: VMC 160

# IfcBuildingElementProxy: VMC 200 (4)
Type - Material: Conduit VMC
Pset_BuildingElementProxyCommon - Reference: VMC 200
Name | In
Galette - Résa - PVC4:VMC 200:3885464 | R+5
Galette - Résa - PVC4:VMC 200:3885465 | R+5
Galette - Résa - PVC4:VMC 200:3885468 | R+5
Galette - Résa - PVC5:VMC 200:3888155 | R+6

# IfcBuildingElementProxy: balcon CSP (9)
Type - Material: Béton, C25/30 balcon
Pset_BuildingElementProxyCommon - Reference: balcon CSP
Name | In
BY_STR_Balcon_CSP_01:balcon CSP:3379347 | R+2
BY_STR_Balcon_CSP_01:balcon CSP:3416831 | R+3
BY_STR_Balcon_CSP_01:balcon CSP:3416857 | R+4
BY_STR_Balcon_CSP_02:balcon CSP:3438774 | R+2
BY_STR_Balcon_CSP_02:balcon CSP:3454208 | R+3
BY_STR_Balcon_CSP_02:balcon CSP:3454218 | R+4
BY_STR_Balcon_CSP_03:balcon CSP:3454286 | R+2
BY_STR_Balcon_CSP_03:balcon CSP:3458394 | R+3
BY_STR_Balcon_CSP_03:balcon CSP:3458404 | R+4

# IfcBuildingElementProxy: balcon préfa type 01 (4)
In: ±0.00
Type - Material: Béton, panneaux préfa 30/37
Pset_BuildingElementProxyCommon - Reference: balcon préfa type 01
Name (BY_STR_Balcon_préfa_01:balcon préfa type 01:...)
2489103
2511600
2511756
2812913

# IfcBuildingElementProxy: balcon préfa type 02 (4)
In: ±0.00
Type - Material: Béton, panneaux préfa 30/37
Pset_BuildingElementProxyCommon - Reference: balcon préfa type 02
Name (BY_STR_Balcon_préfa_02:balcon préfa type 02:...)
2481793
2511897
2812935
2815784

# IfcBuildingElementProxy: balcon préfa type 03 (4)
In: ±0.00
Type - Material: Béton, panneaux préfa 30/37
Pset_BuildingElementProxyCommon - Reference: balcon préfa type 03
Name (BY_STR_Balcon_préfa_03:balcon préfa type 03:...)
2515557
2516323
2516331
2516339

# IfcBuildingElementProxy: balcon préfa type 04 (4)
In: ±0.00
Type - Material: Béton, panneaux préfa 30/37
Pset_BuildingElementProxyCommon - Reference: balcon préfa type 04
Name (BY_STR_Balcon_préfa_04:balcon préfa type 04:...)
2515875
2516467
2516475
2516483

# IfcBuildingElementProxy: balcon préfa type 05 (4)
In: ±0.00
Type - Material: Béton, panneaux préfa 30/37
Pset_BuildingElementProxyCommon - Reference: balcon préfa type 05
Name (BY_STR_Balcon_préfa_05:balcon préfa type 05:...)
2516661
2517190
2517198
2517206

# IfcBuildingElementProxy: balcon préfa type 06 (3)
In: ±0.00
Type - Material: Béton, panneaux préfa 30/37
Pset_BuildingElementProxyCommon - Reference: balcon préfa type 06
Name (BY_STR_Balcon_préfa_06:balcon préfa type 06:...)
2517265
2517844
2517854

# IfcBuildingElementProxy: balcon préfa type 07, BY_STR_Balcon_préfa_07:balcon préfa type 07:2517864
In: ±0.00
Type - Material: Béton, panneaux préfa 30/37
Pset_BuildingElementProxyCommon - Reference: balcon préfa type 07

# IfcBuildingElementProxy: balcon préfa type 08 (4)
In: ±0.00
Type - Material: Béton, panneaux préfa 30/37
Pset_BuildingElementProxyCommon - Reference: balcon préfa type 08
Name (BY_STR_Balcon_préfa_08:balcon préfa type 08:...)
2518226
2518861
2518869
2518877

# IfcBuildingElementProxy: balcon préfa type 09 (2)
In: ±0.00
Type - Material: Béton, panneaux préfa 30/37
Pset_BuildingElementProxyCommon - Reference: balcon préfa type 09
Name (BY_STR_Balcon_préfa_09-10:balcon préfa type 09:...)
2818525
2826590

# IfcBuildingElementProxy: balcon préfa type 10 (2)
In: ±0.00
Type - Material: Béton, panneaux préfa 30/37
Pset_BuildingElementProxyCommon - Reference: balcon préfa type 10
Name (BY_STR_Balcon_préfa_09-10:balcon préfa type 10:...)
2825859
2826591

# IfcBuildingElementProxy: Ø100 (8)
In: Ac RDC
Type - Material: BBGO_Résa
Pset_BuildingElementProxyCommon - Reference: Ø100
Name (BBGO-Résa circ dalle:Ø100:...)
3779169
3780288
3781215
3781447
3782179
3782914
3783829
3783977

# IfcBuildingElementProxy: Ø110 (64)
Type - Material: BBGO_Résa
Pset_BuildingElementProxyCommon - Reference: Ø110
Name (BBGO-Résa circ dalle:Ø110:...) | In
3277480 | Ac RDC
3277774 | Ac RDC
3277917 | Ac RDC
3278327 | Ac RDC
3278410 | Ac RDC
3278462 | Ac RDC
3278512 | Ac RDC
3372728 | Ac RDC
3373196 | Ac RDC
3466640 | Ac RDC
3466641 | Ac RDC
3466662 | Ac RDC
3466675 | Ac RDC
3466791 | Ac RDC
3466826 | Ac RDC
3571660 | Ac RDC
3571668 | Ac RDC
3572179 | Ac RDC
3572299 | Ac RDC
3572750 | Ac RDC
3573147 | Ac RDC
3573525 | Ac RDC
3573721 | Ac RDC
3574477 | Ac RDC
3574855 | Ac RDC
3575281 | Ac RDC
3575660 | Ac RDC
3576043 | Ac RDC
3576645 | Ac RDC
3579838 | R+2
3779015 | Ac RDC
3779072 | Ac RDC
3779226 | Ac RDC
3779238 | Ac RDC
3779497 | Ac RDC
3779765 | Ac RDC
3779916 | Ac RDC
3780022 | Ac RDC
3780165 | Ac RDC
3780270 | Ac RDC
3780485 | Ac RDC
3780580 | Ac RDC
3780776 | Ac RDC
3780998 | Ac RDC
3781054 | Ac RDC
3781193 | Ac RDC
3781201 | Ac RDC
3781728 | Ac RDC
3781780 | Ac RDC
3781954 | Ac RDC
3782124 | Ac RDC
3782320 | Ac RDC
3782787 | Ac RDC
3782795 | Ac RDC
3782857 | Ac RDC
3783338 | Ac RDC
3783348 | Ac RDC
3783408 | Ac RDC
3783640 | Ac RDC
3783689 | Ac RDC
3783819 | Ac RDC
3783917 | Ac RDC
3783976 | Ac RDC
3784043 | Ac RDC

# IfcBuildingElementProxy: Ø140, BBGO-Résa circ dalle:Ø140:3781181
In: Ac RDC
Type - Material: BBGO_Résa
Pset_BuildingElementProxyCommon - Reference: Ø140

# IfcBuildingElementProxy: Ø160 (8)
In: Ac R+2
Type - Material: BBGO_Résa
Pset_BuildingElementProxyCommon - Reference: Ø160
Name (BBGO-Résa circ dalle:Ø160:...)
2825993
2826451
2826541
2826542
2826592
2826593
2826594
2826595

# IfcBuildingElementProxy: Ø30 (8)
In: Ac RDC
Type - Material: BBGO_Résa
Pset_BuildingElementProxyCommon - Reference: Ø30
Name (BBGO-Résa circ dalle:Ø30:...)
3779747
3780637
3781559
3781648
3782024
3782415
3782613
3782659

# IfcBuildingElementProxy: Ø40 (19)
In: Ac RDC
Type - Material: BBGO_Résa
Pset_BuildingElementProxyCommon - Reference: Ø40
Name (BBGO-Résa circ dalle:Ø40:...)
3778940
3779479
3779487
3779621
3779757
3779918
3779983
3780121
3780129
3780139
3780147
3780929
3781834
3782521
3782575
3782585
3782601
3782711
3783240

# IfcBuildingElementProxy: Ø50 (4)
In: Ac RDC
Type - Material: BBGO_Résa
Pset_BuildingElementProxyCommon - Reference: Ø50
Name (BBGO-Résa circ dalle:Ø50:...)
3779611
3779917
3780796
3783126

# IfcBuildingElementProxy: Ø90 (9)
In: Ac RDC
Type - Material: BBGO_Résa
Pset_BuildingElementProxyCommon - Reference: Ø90
Name (BBGO-Résa circ dalle:Ø90:...)
3779104
3780280
3780786
3781223
3781492
3782132
3782906
3783837
3783978

# IfcColumn: 16x43 (2)
Type - ElementType: 16x43; PredefinedType: COLUMN; Material: Béton, C25/30
Pset_ColumnCommon - LoadBearing: yes; IsExternal: no; Reference: 16x43
Name (BBGO-Poteau rect:16x43:...) | In
1467205 | R+4
1471585 | R+3

# IfcColumn: 18x30 (4)
Type - ElementType: 18x30; PredefinedType: COLUMN; Material: Béton, C25/30
Pset_ColumnCommon - LoadBearing: yes; IsExternal: no; Reference: 18x30
Name (BBGO-Poteau rect:18x30:...) | In
1160062 | R+1
1160148 | R+1
1286003 | R+2
1286006 | R+2

# IfcColumn: 18x67 (2)
Type - ElementType: 18x67; PredefinedType: COLUMN; Material: Béton, C25/30
Pset_ColumnCommon - LoadBearing: yes; IsExternal: no; Reference: 18x67
Name (BBGO-Poteau rect:18x67:...) | In
1304883 | R+3
1305832 | R+4

# IfcColumn: 30x40 (6)
Type - ElementType: 30x40; PredefinedType: COLUMN; Material: Béton, C25/30
Pset_ColumnCommon - LoadBearing: yes; IsExternal: no; Reference: 30x40
Name (BBGO-Poteau rect:30x40:...) | In
1366967 | +3.74
1367255 | +3.74
1367364 | +3.74
1397691 | +3.74
1400000 | +3.74
3479440 | +3.77

# IfcColumn: 35x40 (4)
Type - ElementType: 35x40; PredefinedType: COLUMN; Material: Béton, C25/30
Pset_ColumnCommon - LoadBearing: yes; IsExternal: no; Reference: 35x40
Name (BBGO-Poteau rect:35x40:...) | In
1364491 | +3.50
1364689 | +3.50
1386517 | +3.74
1386593 | +3.74

# IfcColumn: 40x40 (3)
Type - ElementType: 40x40; PredefinedType: COLUMN; Material: Béton, C25/30
Pset_ColumnCommon - LoadBearing: yes; IsExternal: no; Reference: 40x40
Name (BBGO-Poteau rect:40x40:...) | In
1362669 | +3.77
1362885 | +3.66
1391469 | +3.66

# IfcColumn: Ø20 (2)
Type - ElementType: Ø20; PredefinedType: COLUMN; Material: Béton, C25/30
Pset_ColumnCommon - LoadBearing: yes; IsExternal: no; Reference: Ø20
Name (BBGO-Poteau circ:Ø20:...) | In
1305180 | R+3
1305835 | R+4

# IfcColumn: Ø25, BBGO-Poteau circ:Ø25:1159884
In: R+1
Type - ElementType: Ø25; PredefinedType: COLUMN; Material: Béton, C25/30
Pset_ColumnCommon - LoadBearing: yes; IsExternal: no; Reference: Ø25

# IfcColumn: Ø30 (18)
Type - ElementType: Ø30; PredefinedType: COLUMN; Material: Béton, panneaux préfa 30/37
Pset_ColumnCommon - LoadBearing: yes; IsExternal: no; Reference: Ø30
Name (BBGO-Poteau circ:Ø30:...) | In
3687305 | R+4
3687308 | R+3
3687311 | R+2
3687314 | R+1
3687317 | +3.66
3687320 | R+5
3687323 | R+4
3687326 | R+3
3687329 | R+2
3687332 | R+1
3687335 | +3.74
3687338 | R+5
3687341 | R+4
3687344 | R+3
3687347 | R+2
3687350 | R+1
3687353 | +3.58
3687356 | R+5

# IfcColumn: Ø35, BBGO-Poteau circ:Ø35:1351864
In: +3.66
Type - ElementType: Ø35; PredefinedType: COLUMN; Material: Béton, C25/30
Pset_ColumnCommon - LoadBearing: yes; IsExternal: no; Reference: Ø35

# IfcColumn: Ø40 (9)
Type - ElementType: Ø40; PredefinedType: COLUMN; Material: Béton, C25/30
Pset_ColumnCommon - LoadBearing: yes; IsExternal: no; Reference: Ø40
Name (BBGO-Poteau circ:Ø40:...) | In
1365881 | +3.74
1366090 | +3.74
1366149 | +3.74
1366268 | +3.74
1366288 | +3.74
1366395 | +3.74
1366491 | +3.58
1366611 | +3.50
1406084 | +3.50

# IfcDoor: HB103 (10)
Type - OperationType: SINGLE_SWING_LEFT; ParameterTakesPrecedence: no; Sizeable: no; Material: Finition Peinture - Blanc satiné, Bois - Panneau de porte, Bois - Cadre de porte
Type - Int. Simple:HB103:1279692 - PanelOperation: SWINGING
OverallHeight: 210 cm; OverallWidth: 107 cm
Pset_DoorCommon - IsExternal: no; Reference: HB103; ThermalTransmittance: 3.7021 kg/K/s3
Name (Int. Simple:HB103:...) | In
1279692 | R+1
1282221 | R+1
1286483 | R+2
1286494 | R+2
1295813 | R+3
1295824 | R+3
1305640 | R+4
1305650 | R+4
1310484 | R+5
1310494 | R+5

# IfcDoor: HB103, Int. Simple:HB103:1351959
In: +3.66
Type - OperationType: SINGLE_SWING_LEFT; ParameterTakesPrecedence: no; Sizeable: no; Material: Finition Peinture - Blanc satiné, Bois - Panneau de porte, Bois - Cadre de porte
Type - Int. Simple:HB103:1351959 - PanelOperation: SWINGING
OverallHeight: 210 cm; OverallWidth: 107 cm
Pset_DoorCommon - IsExternal: no; Reference: HB103; ThermalTransmittance: 3.7021 kg/K/s3

# IfcDoor: HB103 (5)
Type - OperationType: SINGLE_SWING_RIGHT; ParameterTakesPrecedence: no; Sizeable: no; Material: Finition Peinture - Blanc satiné, Bois - Panneau de porte, Bois - Cadre de porte
Type - Int. Simple:HB103:1309793 - PanelOperation: SWINGING
OverallHeight: 210 cm; OverallWidth: 107 cm
Pset_DoorCommon - IsExternal: no; Reference: HB103; ThermalTransmittance: 3.7021 kg/K/s3
Name (Int. Simple:HB103:...) | In
1309793 | R+4
1309877 | R+3
1309953 | R+2
1310021 | R+1
1310684 | R+5

# IfcDoor: HB103 (2)
Type - OperationType: SINGLE_SWING_RIGHT; ParameterTakesPrecedence: no; Sizeable: no; Material: Finition Peinture - Blanc satiné, Bois - Panneau de porte, Bois - Cadre de porte
Type - Int. Simple:HB103:1351979 - PanelOperation: SWINGING
OverallHeight: 210 cm; OverallWidth: 107 cm
Pset_DoorCommon - IsExternal: no; Reference: HB103; ThermalTransmittance: 3.7021 kg/K/s3
Name (Int. Simple:HB103:...) | In
1351979 | +3.58
1364040 | +3.74

# IfcDoor: HB83 (2)
Type - OperationType: SINGLE_SWING_LEFT; ParameterTakesPrecedence: no; Sizeable: no; Material: Finition Peinture - Blanc satiné, Bois - Panneau de porte, Bois - Cadre de porte
Type - Int. Simple:HB83:1282238 - PanelOperation: SWINGING
OverallHeight: 210 cm; OverallWidth: 87 cm
Pset_DoorCommon - IsExternal: no; Reference: HB83; ThermalTransmittance: 3.7021 kg/K/s3
Name (Int. Simple:HB83:...) | In
1282238 | R+1
1286495 | R+2

# IfcDoor: HB83, Int. Simple:HB83:1372582
In: +3.74
Type - OperationType: SINGLE_SWING_LEFT; ParameterTakesPrecedence: no; Sizeable: no; Material: Finition Peinture - Blanc satiné, Bois - Panneau de porte, Bois - Cadre de porte
Type - Int. Simple:HB83:1372582 - PanelOperation: SWINGING
OverallHeight: 210 cm; OverallWidth: 87 cm
Pset_DoorCommon - IsExternal: no; Reference: HB83; ThermalTransmittance: 3.7021 kg/K/s3

# IfcDoor: HB83 (7)
Type - OperationType: SINGLE_SWING_RIGHT; ParameterTakesPrecedence: no; Sizeable: no; Material: Finition Peinture - Blanc satiné, Bois - Panneau de porte, Bois - Cadre de porte
Type - Int. Simple:HB83:1280321 - PanelOperation: SWINGING
OverallHeight: 210 cm; OverallWidth: 87 cm
Pset_DoorCommon - IsExternal: no; Reference: HB83; ThermalTransmittance: 3.7021 kg/K/s3
Name (Int. Simple:HB83:...) | In
1280321 | R+1
1283031 | R+1
1286488 | R+2
1286502 | R+2
1295832 | R+3
1305654 | R+4
1310498 | R+5

# IfcDoor: HB83 (2)
In: +3.74
Type - OperationType: SINGLE_SWING_RIGHT; ParameterTakesPrecedence: no; Sizeable: no; Material: Finition Peinture - Blanc satiné, Bois - Panneau de porte, Bois - Cadre de porte
Type - Int. Simple:HB83:1372603 - PanelOperation: SWINGING
OverallHeight: 210 cm; OverallWidth: 87 cm
Pset_DoorCommon - IsExternal: no; Reference: HB83; ThermalTransmittance: 3.7021 kg/K/s3
Name (Int. Simple:HB83:...)
1372603
1372775

# IfcDoor: HB93 (38)
Type - OperationType: SINGLE_SWING_LEFT; ParameterTakesPrecedence: no; Sizeable: no; Material: Finition Peinture - Blanc satiné, Bois - Panneau de porte, Bois - Cadre de porte
Type - Int. Simple:HB93:1279812 - PanelOperation: SWINGING
OverallHeight: 210 cm; OverallWidth: 97 cm
Pset_DoorCommon - IsExternal: no; Reference: HB93; ThermalTransmittance: 3.7021 kg/K/s3
Name (Int. Simple:HB93:...) | In
1279812 | R+1
1279880 | R+1
1280131 | R+1
1280175 | R+1
1281856 | R+1
1282634 | R+1
1286484 | R+2
1286485 | R+2
1286486 | R+2
1286487 | R+2
1286491 | R+2
1286498 | R+2
1295814 | R+3
1295815 | R+3
1295816 | R+3
1295817 | R+3
1295821 | R+3
1295826 | R+3
1295828 | R+3
1301156 | R+3
1305641 | R+4
1305642 | R+4
1305643 | R+4
1305644 | R+4
1305647 | R+4
1305651 | R+4
1305653 | R+4
1305756 | R+4
1310482 | R+5
1310487 | R+5
1310491 | R+5
1310497 | R+5
1317243 | R+5
1359741 | +3.58
1363770 | +3.66
1364347 | +3.74
1384293 | +3.50
3528709 | +3.66

# IfcDoor: HB93 (5)
In: +3.58
Type - OperationType: SINGLE_SWING_LEFT; ParameterTakesPrecedence: no; Sizeable: no; Material: Finition Peinture - Blanc satiné, Bois - Panneau de porte, Bois - Cadre de porte
Type - Int. Simple:HB93:1372898 - PanelOperation: SWINGING
OverallHeight: 210 cm; OverallWidth: 97 cm
Pset_DoorCommon - IsExternal: no; Reference: HB93; ThermalTransmittance: 3.7021 kg/K/s3
Name (Int. Simple:HB93:...)
1372898
1372979
1373019
1373040
3630001

# IfcDoor: HB93 (29)
Type - OperationType: SINGLE_SWING_RIGHT; ParameterTakesPrecedence: no; Sizeable: no; Material: Finition Peinture - Blanc satiné, Bois - Panneau de porte, Bois - Cadre de porte
Type - Int. Simple:HB93:1275748 - PanelOperation: SWINGING
OverallHeight: 210 cm; OverallWidth: 97 cm
Pset_DoorCommon - IsExternal: no; Reference: HB93; ThermalTransmittance: 3.7021 kg/K/s3
Name (Int. Simple:HB93:...) | In
1275748 | R+1
1282003 | R+1
1282161 | R+1
1282371 | R+1
1282427 | R+1
1282959 | R+1
1286481 | R+2
1286492 | R+2
1286493 | R+2
1286496 | R+2
1286497 | R+2
1286501 | R+2
1295811 | R+3
1295822 | R+3
1295823 | R+3
1295827 | R+3
1305638 | R+4
1305648 | R+4
1305649 | R+4
1305652 | R+4
1310485 | R+5
1310492 | R+5
1310496 | R+5
1330330 | R+5
1351957 | +3.66
1367482 | +3.74
1373279 | +3.58
3528985 | +3.74
3529146 | ±0.00

# IfcDoor: HB93, Int. Simple:HB93:1310493
In: R+5
Type - OperationType: SINGLE_SWING_RIGHT; ParameterTakesPrecedence: no; Sizeable: no; Material: Finition Peinture - Blanc satiné, Bois - Panneau de porte, Bois - Cadre de porte
Type - Int. Simple:HB93:1310493 - PanelOperation: SWINGING
OverallHeight: 210 cm; OverallWidth: 97 cm
Pset_DoorCommon - IsExternal: no; Reference: HB93; ThermalTransmittance: 3.7021 kg/K/s3

# IfcDoor: HB93 (2)
Type - OperationType: SINGLE_SWING_RIGHT; ParameterTakesPrecedence: no; Sizeable: no; Material: Finition Peinture - Blanc satiné, Bois - Panneau de porte, Bois - Cadre de porte
Type - Int. Simple:HB93:1368847 - PanelOperation: SWINGING
OverallHeight: 210 cm; OverallWidth: 97 cm
Pset_DoorCommon - IsExternal: no; Reference: HB93; ThermalTransmittance: 3.7021 kg/K/s3
Name (Int. Simple:HB93:...) | In
1368847 | +3.74
1373000 | +3.58

# IfcDoor: PP (1.23m x 2.04m), Int. Tierce:PP (1.23m x 2.04m):1368826
In: +3.74
Type - OperationType: DOUBLE_DOOR_SINGLE_SWING; ParameterTakesPrecedence: no; Sizeable: no; Material: Finition Peinture - Blanc satiné, Bois - Panneau de porte, Bois - Cadre de porte
Type - Int. Tierce:PP (1.23m x 2.04m):1368826 - PanelOperation: SWINGING
OverallHeight: 207.5 cm; OverallWidth: 145 cm
Pset_DoorCommon - IsExternal: no; Reference: PP (1.23m x 2.04m); ThermalTransmittance: 5.5617 kg/K/s3

# IfcElementAssembly: Assemblage Modèles génériques:BALCON TYPE 01 (4)
In: ±0.00
PredefinedType: USERDEFINED
Name (Assemblage Modèles génériques:BALCON TYPE 01:...)
2653660
2812641
2812780
2812839

# IfcElementAssembly: Assemblage Modèles génériques:BALCON TYPE 02 (4)
In: ±0.00
PredefinedType: USERDEFINED
Name (Assemblage Modèles génériques:BALCON TYPE 02:...)
2722468
2812642
2812863
2815785

# IfcElementAssembly: Assemblage Modèles génériques:BALCON TYPE 03 (4)
In: ±0.00
PredefinedType: USERDEFINED
Name (Assemblage Modèles génériques:BALCON TYPE 03:...)
2723130
2812626
2812627
2812628

# IfcElementAssembly: Assemblage Modèles génériques:BALCON TYPE 04 (4)
In: ±0.00
PredefinedType: USERDEFINED
Name (Assemblage Modèles génériques:BALCON TYPE 04:...)
2723204
2812629
2812630
2812631

# IfcElementAssembly: Assemblage Modèles génériques:BALCON TYPE 05 (4)
In: ±0.00
PredefinedType: USERDEFINED
Name (Assemblage Modèles génériques:BALCON TYPE 05:...)
2723247
2812632
2812633
2812634

# IfcElementAssembly: Assemblage Modèles génériques:BALCON TYPE 06 (3)
In: ±0.00
PredefinedType: USERDEFINED
Name (Assemblage Modèles génériques:BALCON TYPE 06:...)
2723290
2812639
2812640

# IfcElementAssembly: Assemblage Modèles génériques:BALCON TYPE 07, Assemblage Modèles génériques:BALCON TYPE 07:2807757
In: ±0.00
PredefinedType: USERDEFINED

# IfcElementAssembly: Assemblage Modèles génériques:BALCON TYPE 08 (4)
In: ±0.00
PredefinedType: USERDEFINED
Name (Assemblage Modèles génériques:BALCON TYPE 08:...)
2723333
2812636
2812637
2812638

# IfcElementAssembly: Assemblage Modèles génériques:BALCON TYPE 09 (2)
In: ±0.00
PredefinedType: USERDEFINED
Name (Assemblage Modèles génériques:BALCON TYPE 09:...)
2826638
2826658

# IfcElementAssembly: Assemblage Modèles génériques:BALCON TYPE 10 (2)
In: ±0.00
PredefinedType: USERDEFINED
Name (Assemblage Modèles génériques:BALCON TYPE 10:...)
2826648
2826667

# IfcFlowSegment: Canalisation souple arrondie:Flex - Round (4)
In: +3.66
Type - PredefinedType: FLEXIBLESEGMENT
Pset_DistributionFlowElementCommon - Reference: Flex - Round
Name (Canalisation souple arrondie:Flex - Round:...)
1836723
1872692
2957449
2957451

# IfcFlowSegment: Gaine flexible circulaire:Flex - Round (15)
Type - PredefinedType: FLEXIBLESEGMENT
Pset_DistributionFlowElementCommon - Reference: Flex - Round
Name (Gaine flexible circulaire:Flex - Round:...) | In
1873316 | +3.66
1873637 | +3.66
1873666 | +3.66
1873683 | +3.66
1874782 | +3.77
1927735 | +3.77
1927877 | +3.77
1927888 | +3.77
1928064 | +3.66
1928066 | +3.66
1928070 | +3.66
2957455 | +3.77
2957457 | +3.66
2957459 | +3.77
3478793 | +3.66

# IfcSlab: M_Base-Rectangulaire:100x100x60ht (4)
In: +3.50
PredefinedType: BASESLAB; Material: Béton, C25/30
Pset_SlabCommon - IsExternal: no; PitchAngle: 0 deg; Reference: 100x100x60ht
Name (M_Base-Rectangulaire:100x100x60ht:...)
3116814
3117018
3117027
3117029

# IfcSlab: M_Base-Rectangulaire:235x70x110ht (3)
In: +3.74
PredefinedType: BASESLAB; Material: Béton, C25/30
Pset_SlabCommon - IsExternal: no; Reference: 235x70x110ht
Name (M_Base-Rectangulaire:235x70x110ht:...)
1721600
1723669
1762424

# IfcSlab: M_Base-Rectangulaire:265x70x120ht (5)
PredefinedType: BASESLAB; Material: Béton, C25/30
Pset_SlabCommon - IsExternal: no; Reference: 265x70x120ht
Name (M_Base-Rectangulaire:265x70x120ht:...) | In
1748271 | +3.58
1748574 | +3.58
1751591 | +3.66
1756923 | +3.74
1760657 | +3.66

# IfcSlab: M_Base-Rectangulaire:290x80x130ht (6)
PredefinedType: BASESLAB; Material: Béton, C25/30
Pset_SlabCommon - IsExternal: no; Reference: 290x80x130ht
Name (M_Base-Rectangulaire:290x80x130ht:...) | In
1725128 | +3.74
1725279 | +3.74
1760994 | +3.66
1761044 | +3.66
1761582 | +3.66
1767665 | +3.66

# IfcSlab: M_Base-Rectangulaire:70x70x60ht (32)
PredefinedType: BASESLAB; Material: Béton, C25/30
Pset_SlabCommon - IsExternal: no; Reference: 70x70x60ht
Name (M_Base-Rectangulaire:70x70x60ht:...) | In
1743872 | +3.66
1747670 | +3.74
1747953 | +3.74
1748039 | +3.74
1751981 | +3.74
1752804 | +3.74
1752920 | +3.74
1753054 | +3.74
1753068 | +3.58
1753664 | +3.66
1753796 | +3.74
1753919 | +3.58
1754013 | +3.66
1754247 | +3.66
1755893 | +3.66
1756206 | +3.66
1756531 | +3.74
1756609 | +3.74
1757144 | +3.74
1758173 | +3.74
1758793 | +3.58
1759391 | +3.58
1759627 | +3.50
1761572 | +3.66
1761943 | +3.66
1762889 | +3.74
1762988 | +3.74
1763165 | +3.74
1764499 | +3.66
1764668 | +3.50
1765001 | +3.66
1766274 | +3.50

# IfcSlab: M_Base-Rectangulaire:80x70x15ht, M_Base-Rectangulaire:80x70x15ht:2405827
In: +3.66
PredefinedType: BASESLAB; Material: Béton, C25/30
Pset_SlabCommon - IsExternal: no; PitchAngle: 0 deg; Reference: 80x70x15ht

# IfcSlab: M_Base-Rectangulaire:80x80x70ht (30)
PredefinedType: BASESLAB; Material: Béton, C25/30
Pset_SlabCommon - IsExternal: no; Reference: 80x80x70ht
Name (M_Base-Rectangulaire:80x80x70ht:...) | In
1738541 | +3.66
1747574 | +3.74
1747752 | +3.74
1748093 | +3.74
1748147 | +3.58
1751948 | +3.66
1752340 | +3.74
1752717 | +3.74
1753080 | +3.58
1753096 | +3.58
1753110 | +3.58
1753156 | +3.58
1755508 | +3.66
1756117 | +3.66
1756285 | +3.74
1756964 | +3.74
1758286 | +3.74
1758704 | +3.58
1758964 | +3.58
1759495 | +3.58
1762197 | +3.66
1762662 | +3.74
1763002 | +3.74
1763367 | +3.74
1763467 | +3.58
1763965 | +3.50
1764069 | +3.50
1764378 | +3.66
1764870 | +3.50
1765207 | +3.66

# IfcSlab: Pieux:Ø36/53 (32)
PredefinedType: BASESLAB; Material: B25
Pset_SlabCommon - IsExternal: no; PitchAngle: 0 deg; Reference: Ø36/53
Name (Pieux:Ø36/53:...) | In
1685609 | +3.74
1685749 | +3.74
1686836 | +3.74
1696422 | +3.66
1696792 | +3.66
1696804 | +3.66
1696909 | +3.66
1696959 | +3.66
1697152 | +3.74
1697668 | +3.74
1698863 | +3.74
1700692 | +3.74
1700887 | +3.74
1700916 | +3.74
1701015 | +3.74
1701047 | +3.74
1702284 | +3.74
1702314 | +3.74
1703295 | +3.58
1703304 | +3.58
1703459 | +3.58
1704642 | +3.50
1704933 | +3.50
1706750 | +3.66
1706868 | +3.66
1707759 | +3.50
1716520 | +3.74
1716710 | +3.58
1721523 | +3.74
1723513 | +3.74
1723618 | +3.74
3187005 | +3.58

# IfcSlab: Pieux:Ø41/61 (24)
PredefinedType: BASESLAB; Material: B25
Pset_SlabCommon - IsExternal: no; PitchAngle: 0 deg; Reference: Ø41/61
Name (Pieux:Ø41/61:...) | In
1684181 | +3.66
1684236 | +3.66
1687336 | +3.58
1690904 | +3.66
1691244 | +3.74
1696466 | +3.66
1696580 | +3.66
1696862 | +3.66
1697046 | +3.66
1698781 | +3.74
1701037 | +3.74
1702357 | +3.74
1702417 | +3.58
1702452 | +3.58
1702482 | +3.74
1703013 | +3.58
1703695 | +3.58
1703731 | +3.58
1705587 | +3.58
1721478 | +3.74
1723111 | +3.66
1723447 | +3.58
1723449 | +3.58
2396652 | +3.66

# IfcSlab: Pieux:Ø46/67 (29)
PredefinedType: BASESLAB; Material: B25
Pset_SlabCommon - IsExternal: no; PitchAngle: 0 deg; Reference: Ø46/67
Name (Pieux:Ø46/67:...) | In
1683032 | +3.66
1684493 | +3.66
1685437 | +3.74
1686990 | +3.58
1687373 | +3.58
1696495 | +3.66
1696627 | +3.66
1697012 | +3.66
1697094 | +3.66
1698501 | +3.74
1698888 | +3.74
1700494 | +3.74
1700754 | +3.74
1700973 | +3.74
1702388 | +3.74
1706815 | +3.66
1707365 | +3.50
1707419 | +3.50
1707875 | +3.50
1722990 | +3.66
1723188 | +3.66
1723385 | +3.74
1723387 | +3.74
1723797 | +3.66
2404155 | +3.66
3116685 | +3.50
3116736 | +3.50
3116771 | +3.50
3116773 | +3.50

# IfcSlab: Pieux:Ø51/72 (11)
PredefinedType: BASESLAB; Material: B25
Pset_SlabCommon - IsExternal: no; PitchAngle: 0 deg; Reference: Ø51/72
Name (Pieux:Ø51/72:...) | In
1684697 | +3.74
1687391 | +3.58
1690940 | +3.74
1696782 | +3.66
1697632 | +3.74
1698184 | +3.74
1698820 | +3.74
1702255 | +3.74
1702971 | +3.58
1703301 | +3.58
1706922 | +3.66

# IfcSlab: Sol:Dalle Béton - 10 cm, Sol:Dalle Béton - 10 cm:3629318
In: Ac RDC
PredefinedType: FLOOR; Material: Béton, C25/30 10 cm
Pset_SlabCommon - LoadBearing: yes; IsExternal: no; PitchAngle: 0 deg; Reference: Dalle Béton - 10 cm; ThermalTransmittance: 10.46 kg/K/s3

# IfcSlab: Sol:Dalle Béton - 12 cm (2)
PredefinedType: FLOOR; Material: Béton, C25/30 12 cm
Pset_SlabCommon - LoadBearing: yes; IsExternal: no; Reference: Dalle Béton - 12 cm; ThermalTransmittance: 8.71667 kg/K/s3
Name (Sol:Dalle Béton - 12 cm:...) | In
1830295 | +3.66
3624864 | +3.77 | Pset_SlabCommon - PitchAngle: 0 deg

# IfcSlab: Sol:Dalle Béton - 20 cm (67)
PredefinedType: FLOOR
Pset_SlabCommon - LoadBearing: yes; Reference: Dalle Béton - 20 cm; IsExternal: no; ThermalTransmittance: 5.23 kg/K/s3
Name (Sol:Dalle Béton - 20 cm:...) | In | Material | PitchAngle (deg)
1158692 | R+2 | Béton, C25/30
1158725 | R+2 | Béton, C25/30 20 cm
1158759 | R+2 | Béton, C25/30 20 cm
1285913 | R+3 | Béton, C25/30 20 cm
1285918 | R+3 | Béton, C25/30 20 cm
1285923 | R+3 | Béton, C25/30 20 cm
1285941 | R+3 | Béton, C25/30 20 cm | 0
1285950 | R+3 | Béton, C25/30 20 cm | 0
1285988 | R+3 | Béton, C25/30 20 cm | 0
1286124 | R+3 | Béton, C25/30 20 cm | 0
1295489 | R+4 | Béton, C25/30 20 cm
1295494 | R+4 | Béton, C25/30 20 cm
1295499 | R+4 | Béton, C25/30 20 cm
1305427 | R+5 | Béton, C25/30 20 cm
1305432 | R+5 | Béton, C25/30 20 cm
1305437 | R+5 | Béton, C25/30 20 cm
1310271 | R+6 | Béton, C25/30 20 cm
1310276 | R+6 | Béton, C25/30 20 cm
1310281 | R+6 | Béton, C25/30 20 cm
1335618 | Acrotère | Béton, C25/30 20 cm | 0
1336349 | Acrotère | Béton, C25/30 20 cm | 0
1336389 | Acrotère | Béton, C25/30 20 cm | 0
1412491 | R+1 | Béton, C25/30 20 cm | 0
1413589 | R+1 | Béton, C25/30 20 cm | 0
1413921 | R+1 | Béton, C25/30 20 cm | 0
1414027 | R+1 | Béton, C25/30 20 cm | 0
1420520 | R+1 | Béton, C25/30 20 cm
1420625 | R+1 | Béton, C25/30 20 cm | 0
1423122 | R+1 | Béton, C25/30 20 cm
1423601 | R+1 | Béton, C25/30 20 cm | 0
1423641 | R+1 | Béton, C25/30 20 cm | 0
1423684 | R+1 | Béton, C25/30 20 cm | 0
1423718 | R+1 | Béton, C25/30 20 cm
1423751 | R+1 | Béton, C25/30 20 cm
1427569 | +3.66 | Béton, C25/30 20 cm | 0
1633391 | R+1 | Béton, C25/30 20 cm
1644006 | R+1 | Béton, C25/30 20 cm
1646705 | +3.66 | Béton, C25/30 20 cm | 0
1647227 | +3.50 | Béton, C25/30 20 cm
1648480 | +3.58 | Béton, C25/30 20 cm | 0
1650089 | +3.66 | Béton, C25/30 20 cm
1651364 | +3.74 | Béton, C25/30 20 cm
1651364:2 | +3.74 | Béton, C25/30 20 cm
1674211 | +3.66 | Béton, C25/30 20 cm
1674527 | +3.66 | Béton, C25/30 20 cm
1706949 | +3.58 | Béton, C25/30 20 cm | 0
1707046 | +3.74 | Béton, C25/30 20 cm | 0
1707075 | +3.66 | Béton, C25/30 20 cm | 0
1726250 | +3.66 | Béton, C25/30 20 cm | 0
1727790 | +3.74 | Béton, C25/30 20 cm
1728110 | +3.74 | Béton, C25/30 20 cm
1730123 | +3.58 | Béton, C25/30 20 cm
1936567 | R+5 | Béton, C25/30 20 cm | 0
1939890 | R+2 | Béton, C25/30 20 cm | 0
1939931 | R+2 | Béton, C25/30 20 cm | 0
1939972 | R+2 | Béton, C25/30 20 cm | 0
1940745 | R+1 | Béton, C25/30 20 cm | 0
1940786 | R+1 | Béton, C25/30 20 cm | 0
1940827 | R+1 | Béton, C25/30 20 cm | 0
3688008 | R+5 | Béton, C25/30 20 cm | 0
3688175 | R+5 | Béton, C25/30 20 cm | 0
3688388 | R+4 | Béton, C25/30 20 cm | 0
3688503 | R+4 | Béton, C25/30 20 cm | 0
3688600 | R+4 | Béton, C25/30 20 cm | 0
3688909 | R+3 | Béton, C25/30 20 cm | 0
3689024 | R+3 | Béton, C25/30 20 cm | 0
3689121 | R+3 | Béton, C25/30 20 cm | 0

# IfcSlab: Sol:Dalle Béton - 23 cm (3)
In: R+1
PredefinedType: FLOOR
Pset_SlabCommon - LoadBearing: yes; IsExternal: no; Reference: Dalle Béton - 23 cm; ThermalTransmittance: 4.54783 kg/K/s3
Name (Sol:Dalle Béton - 23 cm:...) | Material
1409199 | Béton, C25/30
1420735 | Béton, C25/30 23 cm
1424747 | Béton, C25/30 23 cm

# IfcSlab: Sol:Dalle Béton - 26 cm, Sol:Dalle Béton - 26 cm:1649771
In: +3.77
PredefinedType: FLOOR; Material: Béton, C25/30 26 cm
Pset_SlabCommon - LoadBearing: yes; IsExternal: no; Reference: Dalle Béton - 26 cm; ThermalTransmittance: 4.02308 kg/K/s3

# IfcSlab: Sol:Dalle Béton - 28 cm, Sol:Dalle Béton - 28 cm:3286397
In: R+1
PredefinedType: FLOOR; Material: Béton, C25/30 28 cm
Pset_SlabCommon - LoadBearing: yes; IsExternal: no; PitchAngle: 0 deg; Reference: Dalle Béton - 28 cm; ThermalTransmittance: 3.73571 kg/K/s3

# IfcSlab: Sol:Dalle Béton - 30 cm (3)
In: R+1
PredefinedType: FLOOR; Material: Béton, C25/30 30 cm
Pset_SlabCommon - LoadBearing: yes; IsExternal: no; Reference: Dalle Béton - 30 cm; ThermalTransmittance: 3.48667 kg/K/s3
Name (Sol:Dalle Béton - 30 cm:...)
1414331
1420396
3286863 | Pset_SlabCommon - PitchAngle: 0 deg

# IfcSlab: Sol:Dalle Béton - 5 cm (2)
PredefinedType: FLOOR; Material: Béton, C25/30 5 cm
Pset_SlabCommon - LoadBearing: yes; IsExternal: no; PitchAngle: 0 deg; Reference: Dalle Béton - 5 cm; ThermalTransmittance: 20.92 kg/K/s3
Name (Sol:Dalle Béton - 5 cm:...) | In
3628426 | +3.74
4004384 | RDC

# IfcSlab: Sol:Dalle transfo existant (2)
In: ±0.00
PredefinedType: FLOOR; Material: Existant 18 cm
Pset_SlabCommon - LoadBearing: yes; IsExternal: no; PitchAngle: 0 deg; Reference: Dalle transfo existant; ThermalTransmittance: 5.81111 kg/K/s3
Name (Sol:Dalle transfo existant:...)
1986979
1987130

# IfcSlab: Sol:Enrobé (8)
PredefinedType: FLOOR
Pset_SlabCommon - IsExternal: no; Reference: Enrobé; LoadBearing: no
Name (Sol:Enrobé:...) | In | Material
1645815 | +3.66 | Site - Asphalte 0.1 cm | Pset_SlabCommon - PitchAngle: 0 deg
1711863 | +3.58 | Site - Asphalte 0.1 cm
1712687 | +3.74 | Site - Asphalte 0.1 cm
1713296 | +3.58 | Site - Asphalte 0.1 cm
1713646 | +3.50 | Site - Asphalte 0.1 cm | Pset_SlabCommon - PitchAngle: 0 deg
1714035 | +3.50 | Site - Asphalte 0.1 cm
1714788 | +3.66 | Site - Asphalte 0.1 cm | Pset_SlabCommon - PitchAngle: 0 deg
1928126 | +3.50

# IfcStair: Escalier:Monobloc-générique:28673 (36)
Name (Escalier:Monobloc-générique:...) | In
1934910 | R+4 | Material: Béton, C25/30
1934910 | R+4 | Pset_StairCommon - IsExternal: no; Reference: Monobloc-générique; NumberOfRiser: 17; NumberOfTreads: 17; RiserHeight: 15.8824 cm; TreadLength: 31.2353 cm
1945899 | +3.74 | Material: Béton, C25/30
1945899 | +3.74 | Pset_StairCommon - IsExternal: no; Reference: Monobloc-générique; NumberOfRiser: 6; NumberOfTreads: 6; RiserHeight: 16.6667 cm; TreadLength: 29.6667 cm
1953812 | +3.58 | Material: Béton, C25/30
1953812 | +3.58 | Pset_StairCommon - IsExternal: no; Reference: Monobloc-générique; NumberOfRiser: 7; NumberOfTreads: 7; RiserHeight: 16.5714 cm; TreadLength: 29.8571 cm
3687745 | R+4 | Material: Béton, C25/30
3687745 | R+4 | Pset_StairCommon - IsExternal: no; Reference: Monobloc-générique; NumberOfRiser: 17; NumberOfTreads: 17; RiserHeight: 15.8824 cm; TreadLength: 31.2353 cm
3688145 | R+4 | Material: Béton, C25/30
3688145 | R+4 | Pset_StairCommon - IsExternal: no; Reference: Monobloc-générique; NumberOfRiser: 17; NumberOfTreads: 17; RiserHeight: 15.8824 cm; TreadLength: 31.2353 cm
3688384 | R+3 | Material: Béton, C25/30
3688384 | R+3 | Pset_StairCommon - IsExternal: no; Reference: Monobloc-générique; NumberOfRiser: 17; NumberOfTreads: 17; RiserHeight: 15.8824 cm; TreadLength: 31.2353 cm
3688473 | R+3 | Material: Béton, C25/30
3688473 | R+3 | Pset_StairCommon - IsExternal: no; Reference: Monobloc-générique; NumberOfRiser: 17; NumberOfTreads: 17; RiserHeight: 15.8824 cm; TreadLength: 31.2353 cm
3688570 | R+3 | Material: Béton, C25/30
3688570 | R+3 | Pset_StairCommon - IsExternal: no; Reference: Monobloc-générique; NumberOfRiser: 17; NumberOfTreads: 17; RiserHeight: 15.8824 cm; TreadLength: 31.2353 cm
3688905 | R+2 | Material: Béton, C25/30
3688905 | R+2 | Pset_StairCommon - IsExternal: no; Reference: Monobloc-générique; NumberOfRiser: 17; NumberOfTreads: 17; RiserHeight: 15.8824 cm; TreadLength: 31.2353 cm
3688994 | R+2 | Material: Béton, C25/30
3688994 | R+2 | Pset_StairCommon - IsExternal: no; Reference: Monobloc-générique; NumberOfRiser: 17; NumberOfTreads: 17; RiserHeight: 15.8824 cm; TreadLength: 31.2353 cm
3689091 | R+2 | Material: Béton, C25/30
3689091 | R+2 | Pset_StairCommon - IsExternal: no; Reference: Monobloc-générique; NumberOfRiser: 17; NumberOfTreads: 17; RiserHeight: 15.8824 cm; TreadLength: 31.2353 cm
3689431 | +3.66 | Material: Béton, C25/30
3689431 | +3.66 | Pset_StairCommon - IsExternal: no; Reference: Monobloc-générique; NumberOfRiser: 16; NumberOfTreads: 16; RiserHeight: 17 cm; TreadLength: 29 cm
3689741 | +3.74 | Material: Béton, C25/30
3689741 | +3.74 | Pset_StairCommon - IsExternal: no; Reference: Monobloc-générique; NumberOfRiser: 16; NumberOfTreads: 16; RiserHeight: 16.625 cm; TreadLength: 29.75 cm
3690039 | +3.58 | Material: Béton, C25/30
3690039 | +3.58 | Pset_StairCommon - IsExternal: no; Reference: Monobloc-générique; NumberOfRiser: 16; NumberOfTreads: 16; RiserHeight: 16.625 cm; TreadLength: 29.75 cm
3690297 | +3.66 | Material: Béton, C25/30
3690297 | +3.66 | Pset_StairCommon - IsExternal: no; Reference: Monobloc-générique; NumberOfRiser: 6; NumberOfTreads: 6; RiserHeight: 17 cm; TreadLength: 29 cm
3690420 | R+1 | Material: Béton, C25/30
3690420 | R+1 | Pset_StairCommon - IsExternal: no; Reference: Monobloc-générique; NumberOfRiser: 17; NumberOfTreads: 17; RiserHeight: 15.8824 cm; TreadLength: 31.2353 cm
3690790 | R+1 | Material: Béton, C25/30
3690790 | R+1 | Pset_StairCommon - IsExternal: no; Reference: Monobloc-générique; NumberOfRiser: 17; NumberOfTreads: 17; RiserHeight: 15.8824 cm; TreadLength: 31.2353 cm
3691165 | R+1 | Material: Béton, C25/30
3691165 | R+1 | Pset_StairCommon - IsExternal: no; Reference: Monobloc-générique; NumberOfRiser: 17; NumberOfTreads: 17; RiserHeight: 15.8824 cm; TreadLength: 31.2353 cm

# IfcWall: Mur de base:Int. Parpaing 100 mm, Mur de base:Int. Parpaing 100 mm:1359017
In: +3.74
Type - PredefinedType: STANDARD; Material: Bloc béton 10 cm
Pset_WallCommon - LoadBearing: yes; ExtendToStructure: no; IsExternal: no; Reference: Int. Parpaing 100 mm; ThermalTransmittance: 10.46 kg/K/s3

# IfcWall: Mur de base:Voile BA 15 (5)
In: +3.66
Type - PredefinedType: STANDARD; Material: Béton, C25/30 15 cm
Pset_WallCommon - LoadBearing: yes; ExtendToStructure: no; IsExternal: yes; Reference: Voile BA 15; ThermalTransmittance: 6.97333 kg/K/s3
Name (Mur de base:Voile BA 15:...)
1830479
1831273
1832586
1832590
1832592

# IfcWall: Mur de base:Voile BA 16, Mur de base:Voile BA 16:1361942
In: +3.66
Type - PredefinedType: STANDARD; Material: Béton, C25/30 16 cm
Pset_WallCommon - LoadBearing: yes; ExtendToStructure: no; IsExternal: yes; Reference: Voile BA 16; ThermalTransmittance: 6.5375 kg/K/s3

# IfcWall: Mur de base:Voile BA 18 (50)
Type - PredefinedType: STANDARD; Material: Béton, C25/30 18 cm
Pset_WallCommon - Reference: Voile BA 18; LoadBearing: yes; ExtendToStructure: no; IsExternal: yes; ThermalTransmittance: 5.81111 kg/K/s3
Name (Mur de base:Voile BA 18:...) | In
1137176 | R+1
1140429 | R+1
1141171 | R+1
1141639 | R+1
1142174 | R+1
1142282 | R+1
1142378 | R+1
1142748 | R+1
1144160 | R+1
1153452 | R+1
1193270 | R+1
1285717 | R+2
1285753 | R+2
1285757 | R+2
1285767 | R+2
1285773 | R+2
1285775 | R+2
1285777 | R+2
1285779 | R+2
1285785 | R+2
1285799 | R+2
1286017 | R+2
1295299 | R+3
1295329 | R+3
1295333 | R+3
1295343 | R+3
1295349 | R+3
1295353 | R+3
1295355 | R+3
1295361 | R+3
1295375 | R+3
1305305 | R+4
1305317 | R+4
1305325 | R+4
1305327 | R+4
1305333 | R+4
1351684 | +3.66
1351686 | +3.66
1351696 | +3.66
1351700 | +3.66
1351762 | +3.58
1351822 | +3.74
1351824 | +3.74
1351828 | +3.74
1351846 | +3.58
1351848 | +3.58
1351951 | +3.66
1355555 | +3.66
1356970 | +3.74
1622488 | +3.66

# IfcWall: Mur de base:premur 18 (59)
Pset_WallCommon - LoadBearing: yes; IsExternal: yes; Reference: premur 18; ThermalTransmittance: 5.81111 kg/K/s3
Name (Mur de base:premur 18:...) | In | ExtendToStructure
1138499 | R+1 | no | Material: Béton, panneaux préfa 30/37 (2), Béton, C25/30
1138679 | R+1 | no | Material: Béton, panneaux préfa 30/37 (2), Béton, C25/30
1139228 | R+1 | no | Material: Béton, panneaux préfa 30/37 (2), Béton, C25/30
1139313 | R+1 | no | Material: Béton, panneaux préfa 30/37 (2), Béton, C25/30
1140326 | R+1 | yes | Material: Béton, panneaux préfa 30/37 (2), Béton, C25/30
1144898 | R+1 | no
1150436 | R+1 | no
1150524 | R+1 | no
1150811 | R+1 | no
1152403 | R+1 | no
1152471 | R+1 | no
1230388 | R+1 | no
1267112 | R+1 | no
1285729 | R+2 | no
1285731 | R+2 | no
1285739 | R+2 | no
1285741 | R+2 | no
1285751 | R+2 | no
1285809 | R+2 | no
1285869 | R+2 | no
1285871 | R+2 | no
1285875 | R+2 | no
1285879 | R+2 | no
1285893 | R+2 | no
1285895 | R+2 | no
1286027 | R+2 | no
1286262 | R+2 | no
1295311 | R+3 | no
1295313 | R+3 | no
1295317 | R+3 | no
1295319 | R+3 | no
1295385 | R+3 | no
1295445 | R+3 | no
1295447 | R+3 | no
1295451 | R+3 | no
1295469 | R+3 | no
1295471 | R+3 | no
1295587 | R+3 | no
1295743 | R+3 | no
1305287 | R+4 | no
1305289 | R+4 | no
1305293 | R+4 | no
1305295 | R+4 | no
1305357 | R+4 | no
1305397 | R+4 | no
1305399 | R+4 | no
1305403 | R+4 | no
1305415 | R+4 | no
1305417 | R+4 | no
1305488 | R+4 | yes
1305606 | R+4 | no
1310131 | R+5 | no
1310450 | R+5 | no
1334872 | R+5 | no
1335212 | R+6 | no
1336467 | R+6 | no
1336469 | R+6 | no
1339564 | R+6 | no
1339568 | R+6 | no

# IfcWall: Mur de base:stepoc 20, Mur de base:stepoc 20:1351885
In: +3.66
Material: Stépoc (2), Béton, C25/30
Pset_WallCommon - LoadBearing: yes; ExtendToStructure: no; IsExternal: yes; Reference: stepoc 20; ThermalTransmittance: 11.6222 kg/K/s3

# IfcWall: Mur de base:stepoc 30, Mur de base:stepoc 30:1351704
In: +3.66
Material: Stépoc (2), Béton, C25/30
Pset_WallCommon - LoadBearing: yes; ExtendToStructure: no; IsExternal: yes; Reference: stepoc 30; ThermalTransmittance: 5.50526 kg/K/s3

# IfcWallStandardCase: Mur de base:Int. Parpaing 100 mm (18)
Type - PredefinedType: STANDARD; Material: Bloc béton 10 cm
Pset_WallCommon - LoadBearing: yes; ExtendToStructure: no; IsExternal: no; Reference: Int. Parpaing 100 mm; ThermalTransmittance: 10.46 kg/K/s3
Name (Mur de base:Int. Parpaing 100 mm:...) | In
1351830 | +3.74
1357058 | +3.74
1357133 | +3.74
1357637 | +3.74
1358942 | +3.74
1359169 | +3.58
1359252 | +3.58
1359270 | +3.58
1359292 | +3.58
1359312 | +3.58
1359490 | +3.58
2343617 | +3.77
3480601 | +3.77
3483345 | +3.77
3628655 | +3.74
3628856 | +3.74
3629015 | +3.74
3629996 | +3.58

# IfcWallStandardCase: Mur de base:Int. Parpaing 150 mm (7)
Type - PredefinedType: STANDARD; Material: Bloc béton 15 cm
Pset_WallCommon - LoadBearing: yes; ExtendToStructure: no; IsExternal: no; Reference: Int. Parpaing 150 mm; ThermalTransmittance: 6.97333 kg/K/s3
Name (Mur de base:Int. Parpaing 150 mm:...) | In
1358498 | +3.74
1358761 | +3.74
1363143 | +3.77
1779905 | +3.77
1780034 | +3.77
2343974 | +3.77
2344249 | +3.66

# IfcWallStandardCase: Mur de base:Mur existant (5)
In: +3.50
Type - PredefinedType: STANDARD; Material: Existant 34 cm
Pset_WallCommon - ExtendToStructure: no; IsExternal: no; LoadBearing: no; Reference: Mur existant; ThermalTransmittance: 3.07647 kg/K/s3
Name (Mur de base:Mur existant:...)
1983971
1984825
1984972
1985224
1988139

# IfcWallStandardCase: Mur de base:Mur transfo existant (4)
In: +3.50
Type - PredefinedType: STANDARD; Material: Existant 18 cm
Pset_WallCommon - LoadBearing: yes; ExtendToStructure: no; IsExternal: no; Reference: Mur transfo existant; ThermalTransmittance: 5.81111 kg/K/s3
Name (Mur de base:Mur transfo existant:...)
1985757
1986015
1986186
1986395

# IfcWallStandardCase: Mur de base:Voile BA 15 (11)
Type - PredefinedType: STANDARD; Material: Béton, C25/30 15 cm
Pset_WallCommon - LoadBearing: yes; ExtendToStructure: no; IsExternal: yes; Reference: Voile BA 15; ThermalTransmittance: 6.97333 kg/K/s3
Name (Mur de base:Voile BA 15:...) | In
1461144 | R+5
1461343 | R+5
1461430 | R+5
1831411 | +3.66
1831823 | +3.66
1833060 | +3.66
1833064 | +3.66
1833066 | +3.66
1834180 | +3.66
1834182 | +3.66
1834184 | +3.66

# IfcWallStandardCase: Mur de base:Voile BA 16 (24)
Type - PredefinedType: STANDARD; Material: Béton, C25/30 16 cm
Pset_WallCommon - LoadBearing: yes; ExtendToStructure: no; IsExternal: yes; Reference: Voile BA 16; ThermalTransmittance: 6.5375 kg/K/s3
Name (Mur de base:Voile BA 16:...) | In
1139551 | R+1
1148513 | R+1
1150227 | R+1
1151443 | R+1
1151738 | R+1
1285745 | R+2
1285853 | R+2
1285867 | R+2
1285881 | R+2
1285885 | R+2
1289612 | R+2
1295321 | R+3
1295443 | R+3
1295457 | R+3
1295461 | R+3
1295976 | R+3
1305297 | R+4
1305395 | R+4
1305409 | R+4
1305411 | R+4
1305664 | R+4
1361931 | +3.66
1361953 | +3.66
2976933 | +3.66

# IfcWallStandardCase: Mur de base:Voile BA 18 (466)
Type - PredefinedType: STANDARD; Material: Béton, C25/30 18 cm
Pset_WallCommon - Reference: Voile BA 18; LoadBearing: yes; ExtendToStructure: no; IsExternal: yes; ThermalTransmittance: 5.81111 kg/K/s3
Name (Mur de base:Voile BA 18:...) | In
1130795 | R+1
1133379 | R+1
1136924 | R+1
1137001 | R+1
1137333 | R+1
1137834 | R+1
1137971 | R+1
1138228 | R+1
1138393 | R+1
1138824 | R+1
1138929 | R+1
1139045 | R+1
1139687 | R+1
1140078 | R+1
1140768 | R+1
1140995 | R+1
1141302 | R+1
1141527 | R+1
1141723 | R+1
1141883 | R+1
1142066 | R+1
1142462 | R+1
1142630 | R+1
1143244 | R+1
1143326 | R+1
1143467 | R+1
1143562 | R+1
1143779 | R+1
1143981 | R+1
1144249 | R+1
1144336 | R+1
1144489 | R+1
1144725 | R+1
1145099 | R+1
1145257 | R+1
1145406 | R+1
1145551 | R+1
1145777 | R+1
1145987 | R+1
1146089 | R+1
1146264 | R+1
1146375 | R+1
1146588 | R+1
1146705 | R+1
1146854 | R+1
1146975 | R+1
1147139 | R+1
1147277 | R+1
1147455 | R+1
1147573 | R+1
1147698 | R+1
1148067 | R+1
1148227 | R+1
1148345 | R+1
1148808 | R+1
1148911 | R+1
1149171 | R+1
1149295 | R+1
1149729 | R+1
1149935 | R+1
1150632 | R+1
1150895 | R+1
1151609 | R+1
1151874 | R+1
1152033 | R+1
1152174 | R+1
1152792 | R+1
1152887 | R+1
1153168 | R+1
1153290 | R+1
1160227 | R+1
1160370 | R+1
1193079 | R+1
1193788 | R+1
1194057 | R+1
1194205 | R+1
1194418 | R+1
1194659 | R+1
1202969 | R+1
1264838 | R+1
1265136 | R+1
1265333 | R+1
1265567 | R+1
1266934 | R+1
1282871 | R+1
1285713 | R+2
1285715 | R+2
1285719 | R+2
1285721 | R+2
1285723 | R+2
1285725 | R+2
1285727 | R+2
1285733 | R+2
1285747 | R+2
1285749 | R+2
1285755 | R+2
1285759 | R+2
1285761 | R+2
1285765 | R+2
1285769 | R+2
1285771 | R+2
1285781 | R+2
1285783 | R+2
1285787 | R+2
1285789 | R+2
1285791 | R+2
1285793 | R+2
1285795 | R+2
1285797 | R+2
1285801 | R+2
1285803 | R+2
1285805 | R+2
1285807 | R+2
1285811 | R+2
1285813 | R+2
1285815 | R+2
1285817 | R+2
1285819 | R+2
1285821 | R+2
1285823 | R+2
1285825 | R+2
1285827 | R+2
1285829 | R+2
1285831 | R+2
1285833 | R+2
1285835 | R+2
1285837 | R+2
1285839 | R+2
1285841 | R+2
1285843 | R+2
1285845 | R+2
1285847 | R+2
1285849 | R+2
1285851 | R+2
1285855 | R+2
1285857 | R+2
1285859 | R+2
1285861 | R+2
1285863 | R+2
1285865 | R+2
1285873 | R+2
1285877 | R+2
1285883 | R+2
1285887 | R+2
1285889 | R+2
1285891 | R+2
1285897 | R+2
1285899 | R+2
1285901 | R+2
1285903 | R+2
1285907 | R+2
1286013 | R+2
1286252 | R+2
1286254 | R+2
1286256 | R+2
1286258 | R+2
1286260 | R+2
1286499 | R+2
1295295 | R+3
1295297 | R+3
1295301 | R+3
1295303 | R+3
1295305 | R+3
1295307 | R+3
1295309 | R+3
1295315 | R+3
1295323 | R+3
1295325 | R+3
1295331 | R+3
1295337 | R+3
1295341 | R+3
1295345 | R+3
1295347 | R+3
1295357 | R+3
1295359 | R+3
1295363 | R+3
1295365 | R+3
1295367 | R+3
1295369 | R+3
1295371 | R+3
1295373 | R+3
1295377 | R+3
1295379 | R+3
1295381 | R+3
1295383 | R+3
1295387 | R+3
1295389 | R+3
1295391 | R+3
1295393 | R+3
1295395 | R+3
1295397 | R+3
1295401 | R+3
1295405 | R+3
1295407 | R+3
1295409 | R+3
1295411 | R+3
1295413 | R+3
1295417 | R+3
1295421 | R+3
1295423 | R+3
1295431 | R+3
1295433 | R+3
1295435 | R+3
1295437 | R+3
1295439 | R+3
1295449 | R+3
1295453 | R+3
1295467 | R+3
1295473 | R+3
1295475 | R+3
1295477 | R+3
1295479 | R+3
1295579 | R+3
1295733 | R+3
1295735 | R+3
1295737 | R+3
1295739 | R+3
1295741 | R+3
1304053 | R+3
1305271 | R+4
1305273 | R+4
1305275 | R+4
1305277 | R+4
1305279 | R+4
1305281 | R+4
1305283 | R+4
1305285 | R+4
1305291 | R+4
1305299 | R+4
1305301 | R+4
1305307 | R+4
1305309 | R+4
1305311 | R+4
1305315 | R+4
1305319 | R+4
1305321 | R+4
1305323 | R+4
1305329 | R+4
1305331 | R+4
1305335 | R+4
1305337 | R+4
1305339 | R+4
1305341 | R+4
1305343 | R+4
1305345 | R+4
1305347 | R+4
1305349 | R+4
1305351 | R+4
1305353 | R+4
1305355 | R+4
1305359 | R+4
1305361 | R+4
1305363 | R+4
1305365 | R+4
1305367 | R+4
1305369 | R+4
1305371 | R+4
1305373 | R+4
1305375 | R+4
1305377 | R+4
1305379 | R+4
1305381 | R+4
1305383 | R+4
1305385 | R+4
1305387 | R+4
1305389 | R+4
1305391 | R+4
1305393 | R+4
1305401 | R+4
1305405 | R+4
1305413 | R+4
1305419 | R+4
1305421 | R+4
1305423 | R+4
1305596 | R+4
1305598 | R+4
1305600 | R+4
1305602 | R+4
1305604 | R+4
1305830 | R+4
1310123 | R+5
1310125 | R+5
1310129 | R+5
1310135 | R+5
1310143 | R+5
1310145 | R+5
1310149 | R+5
1310151 | R+5
1310153 | R+5
1310155 | R+5
1310159 | R+5
1310161 | R+5
1310163 | R+5
1310165 | R+5
1310167 | R+5
1310169 | R+5
1310171 | R+5
1310173 | R+5
1310175 | R+5
1310177 | R+5
1310183 | R+5
1310185 | R+5
1310189 | R+5
1310197 | R+5
1310199 | R+5
1310205 | R+5
1310211 | R+5
1310215 | R+5
1310217 | R+5
1310219 | R+5
1310221 | R+5
1310225 | R+5
1310227 | R+5
1310229 | R+5
1310231 | R+5
1310233 | R+5
1310245 | R+5
1310257 | R+5
1310263 | R+5
1310265 | R+5
1310267 | R+5
1310442 | R+5
1310444 | R+5
1310446 | R+5
1310448 | R+5
1310574 | R+5
1313752 | R+5
1313886 | R+5
1313913 | R+5
1314506 | R+5
1314935 | R+5
1315171 | R+5
1315954 | R+6
1315956 | R+6
1315958 | R+6
1315960 | R+6
1316344 | R+5
1316346 | R+5
1316699 | R+5
1316886 | R+5
1316993 | R+5
1317381 | R+5
1317653 | R+5
1317899 | R+5
1327179 | R+6
1327183 | R+6
1327196 | R+6
1327202 | R+6
1327205 | R+6
1327207 | R+6
1327210 | R+6
1329158 | R+5
1329160 | R+5
1329324 | R+5
1330060 | R+5
1330751 | R+5
1333981 | R+6
1334001 | R+6
1334005 | R+6
1334009 | R+6
1337313 | R+5
1351676 | +3.66
1351682 | +3.66
1351692 | +3.66
1351694 | +3.66
1351698 | +3.66
1351710 | +3.66
1351748 | +3.50
1351758 | +3.58
1351760 | +3.58
1351770 | +3.58
1351772 | +3.58
1351774 | +3.58
1351782 | +3.74
1351784 | +3.74
1351786 | +3.74
1351788 | +3.74
1351790 | +3.74
1351798 | +3.66
1351800 | +3.66
1351806 | +3.74
1351808 | +3.74
1351812 | +3.74
1351814 | +3.74
1351818 | +3.74
1351820 | +3.74
1351826 | +3.74
1351832 | +3.74
1351834 | +3.74
1351838 | +3.74
1351844 | +3.58
1351850 | +3.58
1351852 | +3.58
1351854 | +3.66
1351947 | +3.50
1351949 | +3.66
1351953 | +3.58
1351955 | +3.58
1351975 | +3.58
1354192 | +3.66
1354405 | +3.66
1354483 | +3.66
1354563 | +3.66
1354899 | +3.66
1355484 | +3.66
1355663 | +3.66
1355930 | +3.66
1356442 | +3.74
1356745 | +3.74
1357322 | +3.74
1357739 | +3.74
1357845 | +3.74
1358887 | +3.58
1359609 | +3.58
1359739 | +3.58
1360304 | +3.50
1360385 | +3.50
1360451 | +3.58
1360608 | +3.58
1360810 | +3.58
1361113 | +3.58
1361440 | +3.58
1361699 | +3.66
1361757 | +3.66
1362006 | +3.66
1367215 | +3.74
1395612 | +3.74
1397471 | R+1
1400481 | R+1
1406836 | R+1
1406913 | R+1
1412436 | R+1
1429467 | +3.50
1469851 | R+5
1476867 | R+5
1480073 | R+6
1523812 | R+5
1576036 | R+5
1576207 | R+5
1576399 | R+5
1576517 | R+5
1576671 | R+5
1603245 | R+1
1605293 | R+1
1606133 | R+1
1616483 | +3.58
1641742 | +3.74
1644378 | +3.58
1648191 | +3.50
1676884 | +3.66
1773957 | +3.66
1781624 | +3.74
1782089 | +3.74
1785286 | +3.66
1867764 | R+3
1867766 | R+3
1867768 | R+3
1867770 | R+3
2028578 | R+1
2028867 | R+2
2028963 | R+3
2029099 | R+5
2029206 | R+6
2029290 | R+4
3324355 | R+1
3324774 | R+1

# IfcWallStandardCase: Mur de base:Voile BA 20, Mur de base:Voile BA 20:1833062
In: +3.66
Type - PredefinedType: STANDARD; Material: Béton, C25/30 20 cm
Pset_WallCommon - LoadBearing: yes; ExtendToStructure: no; IsExternal: yes; Reference: Voile BA 20; ThermalTransmittance: 5.23 kg/K/s3

# IfcWallStandardCase: Mur de base:premur 18 (36)
Material: Béton, panneaux préfa 30/37 5.5 cm, Béton, C25/30 7 cm, Béton, panneaux préfa 30/37 5.5 cm
Pset_WallCommon - LoadBearing: yes; IsExternal: yes; Reference: premur 18; ThermalTransmittance: 5.81111 kg/K/s3
Name (Mur de base:premur 18:...) | In | ExtendToStructure
1141403 | R+1 | no
1151162 | R+1 | no
1285763 | R+2 | no
1295327 | R+3 | yes
1295339 | R+3 | no
1295455 | R+3 | no
1305303 | R+4 | yes
1305313 | R+4 | no
1305407 | R+4 | no
1310133 | R+5 | no
1310137 | R+5 | no
1310139 | R+5 | no
1310147 | R+5 | no
1310157 | R+5 | no
1310201 | R+5 | no
1310241 | R+5 | no
1310243 | R+5 | no
1310247 | R+5 | no
1310249 | R+5 | no
1310251 | R+5 | no
1310259 | R+5 | no
1310261 | R+5 | no
1310332 | R+5 | no
1314168 | R+5 | no
1315962 | R+6 | no
1327177 | R+6 | no
1330673 | R+5 | no
1333987 | R+6 | no
1335208 | R+6 | no
1335210 | R+6 | no
1335907 | R+5 | no
1336145 | R+5 | no
1336543 | R+6 | no
1339326 | R+5 | no
1339404 | R+5 | no
1339566 | R+6 | no
